##
## LEF for PtnCells ;
## created by Innovus v15.23-s045_1 on Sat Mar 21 00:23:52 2026
##

VERSION 5.8 ;

BUSBITCHARS "[]" ;
DIVIDERCHAR "/" ;

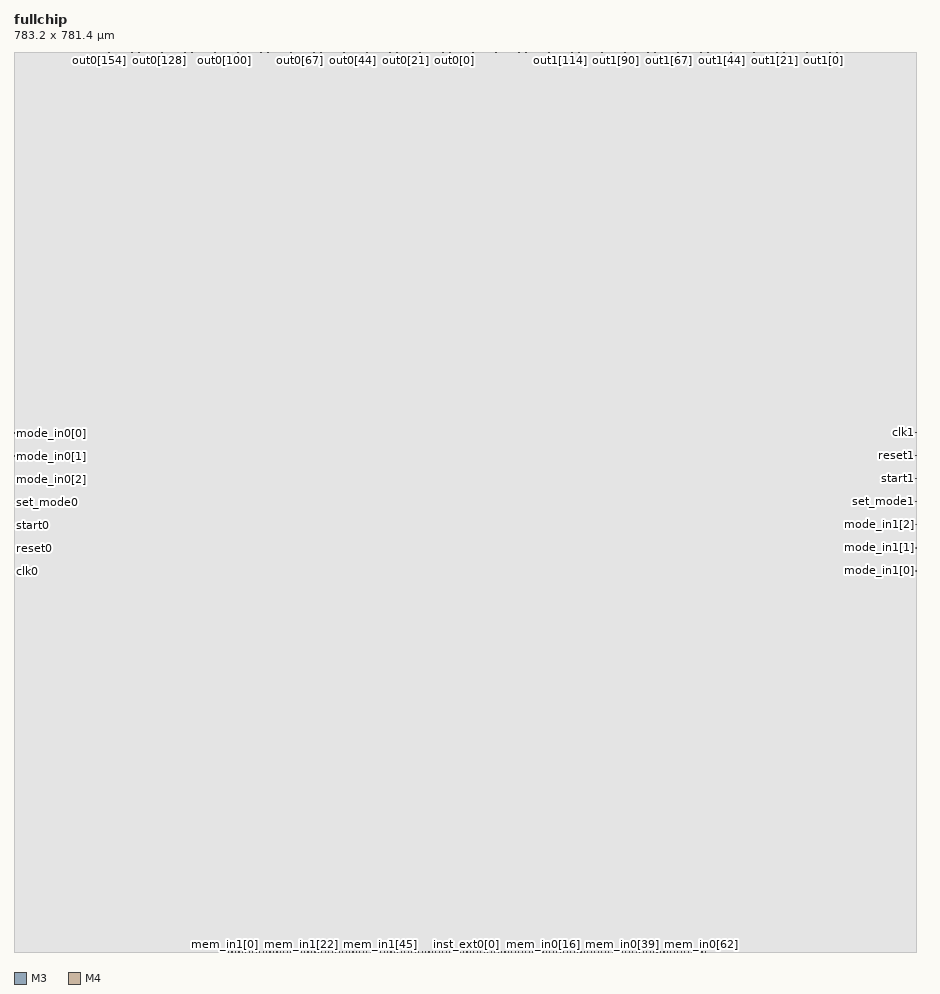
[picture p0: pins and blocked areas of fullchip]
MACRO fullchip
  CLASS BLOCK ;
  SIZE 783.2000 BY 781.4000 ;
  FOREIGN fullchip 0.0000 0.0000 ;
  ORIGIN 0 0 ;
  SYMMETRY X Y R90 ;
  PIN reset0
    DIRECTION INPUT ;
    USE SIGNAL ;
    PORT
      LAYER M3 ;
        RECT 0.0000 350.5500 0.5200 350.6500 ;
    END
  END reset0
  PIN reset1
    DIRECTION INPUT ;
    USE SIGNAL ;
    PORT
      LAYER M3 ;
        RECT 782.6800 430.7500 783.2000 430.8500 ;
    END
  END reset1
  PIN clk0
    DIRECTION INPUT ;
    USE SIGNAL ;
    PORT
      LAYER M3 ;
        RECT 0.0000 330.5500 0.5200 330.6500 ;
    END
  END clk0
  PIN clk1
    DIRECTION INPUT ;
    USE SIGNAL ;
    PORT
      LAYER M3 ;
        RECT 782.6800 450.7500 783.2000 450.8500 ;
    END
  END clk1
  PIN start0
    DIRECTION INPUT ;
    USE SIGNAL ;
    PORT
      LAYER M3 ;
        RECT 0.0000 370.5500 0.5200 370.6500 ;
    END
  END start0
  PIN start1
    DIRECTION INPUT ;
    USE SIGNAL ;
    PORT
      LAYER M3 ;
        RECT 782.6800 410.7500 783.2000 410.8500 ;
    END
  END start1
  PIN set_mode0
    DIRECTION INPUT ;
    USE SIGNAL ;
    PORT
      LAYER M3 ;
        RECT 0.0000 390.5500 0.5200 390.6500 ;
    END
  END set_mode0
  PIN set_mode1
    DIRECTION INPUT ;
    USE SIGNAL ;
    PORT
      LAYER M3 ;
        RECT 782.6800 390.7500 783.2000 390.8500 ;
    END
  END set_mode1
  PIN mode_in0[2]
    DIRECTION INPUT ;
    USE SIGNAL ;
    PORT
      LAYER M3 ;
        RECT 0.0000 410.5500 0.5200 410.6500 ;
    END
  END mode_in0[2]
  PIN mode_in0[1]
    DIRECTION INPUT ;
    USE SIGNAL ;
    PORT
      LAYER M3 ;
        RECT 0.0000 430.5500 0.5200 430.6500 ;
    END
  END mode_in0[1]
  PIN mode_in0[0]
    DIRECTION INPUT ;
    USE SIGNAL ;
    PORT
      LAYER M3 ;
        RECT 0.0000 450.5500 0.5200 450.6500 ;
    END
  END mode_in0[0]
  PIN mode_in1[2]
    DIRECTION INPUT ;
    USE SIGNAL ;
    PORT
      LAYER M3 ;
        RECT 782.6800 370.7500 783.2000 370.8500 ;
    END
  END mode_in1[2]
  PIN mode_in1[1]
    DIRECTION INPUT ;
    USE SIGNAL ;
    PORT
      LAYER M3 ;
        RECT 782.6800 350.7500 783.2000 350.8500 ;
    END
  END mode_in1[1]
  PIN mode_in1[0]
    DIRECTION INPUT ;
    USE SIGNAL ;
    PORT
      LAYER M3 ;
        RECT 782.6800 330.7500 783.2000 330.8500 ;
    END
  END mode_in1[0]
  PIN mem_in0[63]
    DIRECTION INPUT ;
    USE SIGNAL ;
    PORT
      LAYER M4 ;
        RECT 600.2500 0.0000 600.3500 0.5200 ;
    END
  END mem_in0[63]
  PIN mem_in0[62]
    DIRECTION INPUT ;
    USE SIGNAL ;
    PORT
      LAYER M4 ;
        RECT 597.2500 0.0000 597.3500 0.5200 ;
    END
  END mem_in0[62]
  PIN mem_in0[61]
    DIRECTION INPUT ;
    USE SIGNAL ;
    PORT
      LAYER M4 ;
        RECT 594.2500 0.0000 594.3500 0.5200 ;
    END
  END mem_in0[61]
  PIN mem_in0[60]
    DIRECTION INPUT ;
    USE SIGNAL ;
    PORT
      LAYER M4 ;
        RECT 591.2500 0.0000 591.3500 0.5200 ;
    END
  END mem_in0[60]
  PIN mem_in0[59]
    DIRECTION INPUT ;
    USE SIGNAL ;
    PORT
      LAYER M4 ;
        RECT 588.2500 0.0000 588.3500 0.5200 ;
    END
  END mem_in0[59]
  PIN mem_in0[58]
    DIRECTION INPUT ;
    USE SIGNAL ;
    PORT
      LAYER M4 ;
        RECT 585.2500 0.0000 585.3500 0.5200 ;
    END
  END mem_in0[58]
  PIN mem_in0[57]
    DIRECTION INPUT ;
    USE SIGNAL ;
    PORT
      LAYER M4 ;
        RECT 582.2500 0.0000 582.3500 0.5200 ;
    END
  END mem_in0[57]
  PIN mem_in0[56]
    DIRECTION INPUT ;
    USE SIGNAL ;
    PORT
      LAYER M4 ;
        RECT 579.2500 0.0000 579.3500 0.5200 ;
    END
  END mem_in0[56]
  PIN mem_in0[55]
    DIRECTION INPUT ;
    USE SIGNAL ;
    PORT
      LAYER M4 ;
        RECT 576.2500 0.0000 576.3500 0.5200 ;
    END
  END mem_in0[55]
  PIN mem_in0[54]
    DIRECTION INPUT ;
    USE SIGNAL ;
    PORT
      LAYER M4 ;
        RECT 573.2500 0.0000 573.3500 0.5200 ;
    END
  END mem_in0[54]
  PIN mem_in0[53]
    DIRECTION INPUT ;
    USE SIGNAL ;
    PORT
      LAYER M4 ;
        RECT 570.2500 0.0000 570.3500 0.5200 ;
    END
  END mem_in0[53]
  PIN mem_in0[52]
    DIRECTION INPUT ;
    USE SIGNAL ;
    PORT
      LAYER M4 ;
        RECT 567.2500 0.0000 567.3500 0.5200 ;
    END
  END mem_in0[52]
  PIN mem_in0[51]
    DIRECTION INPUT ;
    USE SIGNAL ;
    PORT
      LAYER M4 ;
        RECT 564.2500 0.0000 564.3500 0.5200 ;
    END
  END mem_in0[51]
  PIN mem_in0[50]
    DIRECTION INPUT ;
    USE SIGNAL ;
    PORT
      LAYER M4 ;
        RECT 561.2500 0.0000 561.3500 0.5200 ;
    END
  END mem_in0[50]
  PIN mem_in0[49]
    DIRECTION INPUT ;
    USE SIGNAL ;
    PORT
      LAYER M4 ;
        RECT 558.2500 0.0000 558.3500 0.5200 ;
    END
  END mem_in0[49]
  PIN mem_in0[48]
    DIRECTION INPUT ;
    USE SIGNAL ;
    PORT
      LAYER M4 ;
        RECT 555.2500 0.0000 555.3500 0.5200 ;
    END
  END mem_in0[48]
  PIN mem_in0[47]
    DIRECTION INPUT ;
    USE SIGNAL ;
    PORT
      LAYER M4 ;
        RECT 552.2500 0.0000 552.3500 0.5200 ;
    END
  END mem_in0[47]
  PIN mem_in0[46]
    DIRECTION INPUT ;
    USE SIGNAL ;
    PORT
      LAYER M4 ;
        RECT 549.2500 0.0000 549.3500 0.5200 ;
    END
  END mem_in0[46]
  PIN mem_in0[45]
    DIRECTION INPUT ;
    USE SIGNAL ;
    PORT
      LAYER M4 ;
        RECT 546.2500 0.0000 546.3500 0.5200 ;
    END
  END mem_in0[45]
  PIN mem_in0[44]
    DIRECTION INPUT ;
    USE SIGNAL ;
    PORT
      LAYER M4 ;
        RECT 543.2500 0.0000 543.3500 0.5200 ;
    END
  END mem_in0[44]
  PIN mem_in0[43]
    DIRECTION INPUT ;
    USE SIGNAL ;
    PORT
      LAYER M4 ;
        RECT 540.2500 0.0000 540.3500 0.5200 ;
    END
  END mem_in0[43]
  PIN mem_in0[42]
    DIRECTION INPUT ;
    USE SIGNAL ;
    PORT
      LAYER M4 ;
        RECT 537.2500 0.0000 537.3500 0.5200 ;
    END
  END mem_in0[42]
  PIN mem_in0[41]
    DIRECTION INPUT ;
    USE SIGNAL ;
    PORT
      LAYER M4 ;
        RECT 534.2500 0.0000 534.3500 0.5200 ;
    END
  END mem_in0[41]
  PIN mem_in0[40]
    DIRECTION INPUT ;
    USE SIGNAL ;
    PORT
      LAYER M4 ;
        RECT 531.2500 0.0000 531.3500 0.5200 ;
    END
  END mem_in0[40]
  PIN mem_in0[39]
    DIRECTION INPUT ;
    USE SIGNAL ;
    PORT
      LAYER M4 ;
        RECT 528.2500 0.0000 528.3500 0.5200 ;
    END
  END mem_in0[39]
  PIN mem_in0[38]
    DIRECTION INPUT ;
    USE SIGNAL ;
    PORT
      LAYER M4 ;
        RECT 525.2500 0.0000 525.3500 0.5200 ;
    END
  END mem_in0[38]
  PIN mem_in0[37]
    DIRECTION INPUT ;
    USE SIGNAL ;
    PORT
      LAYER M4 ;
        RECT 522.2500 0.0000 522.3500 0.5200 ;
    END
  END mem_in0[37]
  PIN mem_in0[36]
    DIRECTION INPUT ;
    USE SIGNAL ;
    PORT
      LAYER M4 ;
        RECT 519.2500 0.0000 519.3500 0.5200 ;
    END
  END mem_in0[36]
  PIN mem_in0[35]
    DIRECTION INPUT ;
    USE SIGNAL ;
    PORT
      LAYER M4 ;
        RECT 516.2500 0.0000 516.3500 0.5200 ;
    END
  END mem_in0[35]
  PIN mem_in0[34]
    DIRECTION INPUT ;
    USE SIGNAL ;
    PORT
      LAYER M4 ;
        RECT 513.2500 0.0000 513.3500 0.5200 ;
    END
  END mem_in0[34]
  PIN mem_in0[33]
    DIRECTION INPUT ;
    USE SIGNAL ;
    PORT
      LAYER M4 ;
        RECT 510.2500 0.0000 510.3500 0.5200 ;
    END
  END mem_in0[33]
  PIN mem_in0[32]
    DIRECTION INPUT ;
    USE SIGNAL ;
    PORT
      LAYER M4 ;
        RECT 507.2500 0.0000 507.3500 0.5200 ;
    END
  END mem_in0[32]
  PIN mem_in0[31]
    DIRECTION INPUT ;
    USE SIGNAL ;
    PORT
      LAYER M4 ;
        RECT 504.2500 0.0000 504.3500 0.5200 ;
    END
  END mem_in0[31]
  PIN mem_in0[30]
    DIRECTION INPUT ;
    USE SIGNAL ;
    PORT
      LAYER M4 ;
        RECT 501.2500 0.0000 501.3500 0.5200 ;
    END
  END mem_in0[30]
  PIN mem_in0[29]
    DIRECTION INPUT ;
    USE SIGNAL ;
    PORT
      LAYER M4 ;
        RECT 498.2500 0.0000 498.3500 0.5200 ;
    END
  END mem_in0[29]
  PIN mem_in0[28]
    DIRECTION INPUT ;
    USE SIGNAL ;
    PORT
      LAYER M4 ;
        RECT 495.2500 0.0000 495.3500 0.5200 ;
    END
  END mem_in0[28]
  PIN mem_in0[27]
    DIRECTION INPUT ;
    USE SIGNAL ;
    PORT
      LAYER M4 ;
        RECT 492.2500 0.0000 492.3500 0.5200 ;
    END
  END mem_in0[27]
  PIN mem_in0[26]
    DIRECTION INPUT ;
    USE SIGNAL ;
    PORT
      LAYER M4 ;
        RECT 489.2500 0.0000 489.3500 0.5200 ;
    END
  END mem_in0[26]
  PIN mem_in0[25]
    DIRECTION INPUT ;
    USE SIGNAL ;
    PORT
      LAYER M4 ;
        RECT 486.2500 0.0000 486.3500 0.5200 ;
    END
  END mem_in0[25]
  PIN mem_in0[24]
    DIRECTION INPUT ;
    USE SIGNAL ;
    PORT
      LAYER M4 ;
        RECT 483.2500 0.0000 483.3500 0.5200 ;
    END
  END mem_in0[24]
  PIN mem_in0[23]
    DIRECTION INPUT ;
    USE SIGNAL ;
    PORT
      LAYER M4 ;
        RECT 480.2500 0.0000 480.3500 0.5200 ;
    END
  END mem_in0[23]
  PIN mem_in0[22]
    DIRECTION INPUT ;
    USE SIGNAL ;
    PORT
      LAYER M4 ;
        RECT 477.2500 0.0000 477.3500 0.5200 ;
    END
  END mem_in0[22]
  PIN mem_in0[21]
    DIRECTION INPUT ;
    USE SIGNAL ;
    PORT
      LAYER M4 ;
        RECT 474.2500 0.0000 474.3500 0.5200 ;
    END
  END mem_in0[21]
  PIN mem_in0[20]
    DIRECTION INPUT ;
    USE SIGNAL ;
    PORT
      LAYER M4 ;
        RECT 471.2500 0.0000 471.3500 0.5200 ;
    END
  END mem_in0[20]
  PIN mem_in0[19]
    DIRECTION INPUT ;
    USE SIGNAL ;
    PORT
      LAYER M4 ;
        RECT 468.2500 0.0000 468.3500 0.5200 ;
    END
  END mem_in0[19]
  PIN mem_in0[18]
    DIRECTION INPUT ;
    USE SIGNAL ;
    PORT
      LAYER M4 ;
        RECT 465.2500 0.0000 465.3500 0.5200 ;
    END
  END mem_in0[18]
  PIN mem_in0[17]
    DIRECTION INPUT ;
    USE SIGNAL ;
    PORT
      LAYER M4 ;
        RECT 462.2500 0.0000 462.3500 0.5200 ;
    END
  END mem_in0[17]
  PIN mem_in0[16]
    DIRECTION INPUT ;
    USE SIGNAL ;
    PORT
      LAYER M4 ;
        RECT 459.2500 0.0000 459.3500 0.5200 ;
    END
  END mem_in0[16]
  PIN mem_in0[15]
    DIRECTION INPUT ;
    USE SIGNAL ;
    PORT
      LAYER M4 ;
        RECT 456.2500 0.0000 456.3500 0.5200 ;
    END
  END mem_in0[15]
  PIN mem_in0[14]
    DIRECTION INPUT ;
    USE SIGNAL ;
    PORT
      LAYER M4 ;
        RECT 453.2500 0.0000 453.3500 0.5200 ;
    END
  END mem_in0[14]
  PIN mem_in0[13]
    DIRECTION INPUT ;
    USE SIGNAL ;
    PORT
      LAYER M4 ;
        RECT 450.2500 0.0000 450.3500 0.5200 ;
    END
  END mem_in0[13]
  PIN mem_in0[12]
    DIRECTION INPUT ;
    USE SIGNAL ;
    PORT
      LAYER M4 ;
        RECT 447.2500 0.0000 447.3500 0.5200 ;
    END
  END mem_in0[12]
  PIN mem_in0[11]
    DIRECTION INPUT ;
    USE SIGNAL ;
    PORT
      LAYER M4 ;
        RECT 444.2500 0.0000 444.3500 0.5200 ;
    END
  END mem_in0[11]
  PIN mem_in0[10]
    DIRECTION INPUT ;
    USE SIGNAL ;
    PORT
      LAYER M4 ;
        RECT 441.2500 0.0000 441.3500 0.5200 ;
    END
  END mem_in0[10]
  PIN mem_in0[9]
    DIRECTION INPUT ;
    USE SIGNAL ;
    PORT
      LAYER M4 ;
        RECT 438.2500 0.0000 438.3500 0.5200 ;
    END
  END mem_in0[9]
  PIN mem_in0[8]
    DIRECTION INPUT ;
    USE SIGNAL ;
    PORT
      LAYER M4 ;
        RECT 435.2500 0.0000 435.3500 0.5200 ;
    END
  END mem_in0[8]
  PIN mem_in0[7]
    DIRECTION INPUT ;
    USE SIGNAL ;
    PORT
      LAYER M4 ;
        RECT 432.2500 0.0000 432.3500 0.5200 ;
    END
  END mem_in0[7]
  PIN mem_in0[6]
    DIRECTION INPUT ;
    USE SIGNAL ;
    PORT
      LAYER M4 ;
        RECT 429.2500 0.0000 429.3500 0.5200 ;
    END
  END mem_in0[6]
  PIN mem_in0[5]
    DIRECTION INPUT ;
    USE SIGNAL ;
    PORT
      LAYER M4 ;
        RECT 426.2500 0.0000 426.3500 0.5200 ;
    END
  END mem_in0[5]
  PIN mem_in0[4]
    DIRECTION INPUT ;
    USE SIGNAL ;
    PORT
      LAYER M4 ;
        RECT 423.2500 0.0000 423.3500 0.5200 ;
    END
  END mem_in0[4]
  PIN mem_in0[3]
    DIRECTION INPUT ;
    USE SIGNAL ;
    PORT
      LAYER M4 ;
        RECT 420.2500 0.0000 420.3500 0.5200 ;
    END
  END mem_in0[3]
  PIN mem_in0[2]
    DIRECTION INPUT ;
    USE SIGNAL ;
    PORT
      LAYER M4 ;
        RECT 417.2500 0.0000 417.3500 0.5200 ;
    END
  END mem_in0[2]
  PIN mem_in0[1]
    DIRECTION INPUT ;
    USE SIGNAL ;
    PORT
      LAYER M4 ;
        RECT 414.2500 0.0000 414.3500 0.5200 ;
    END
  END mem_in0[1]
  PIN mem_in0[0]
    DIRECTION INPUT ;
    USE SIGNAL ;
    PORT
      LAYER M4 ;
        RECT 411.2500 0.0000 411.3500 0.5200 ;
    END
  END mem_in0[0]
  PIN mem_in1[63]
    DIRECTION INPUT ;
    USE SIGNAL ;
    PORT
      LAYER M4 ;
        RECT 372.2500 0.0000 372.3500 0.5200 ;
    END
  END mem_in1[63]
  PIN mem_in1[62]
    DIRECTION INPUT ;
    USE SIGNAL ;
    PORT
      LAYER M4 ;
        RECT 369.2500 0.0000 369.3500 0.5200 ;
    END
  END mem_in1[62]
  PIN mem_in1[61]
    DIRECTION INPUT ;
    USE SIGNAL ;
    PORT
      LAYER M4 ;
        RECT 366.2500 0.0000 366.3500 0.5200 ;
    END
  END mem_in1[61]
  PIN mem_in1[60]
    DIRECTION INPUT ;
    USE SIGNAL ;
    PORT
      LAYER M4 ;
        RECT 363.2500 0.0000 363.3500 0.5200 ;
    END
  END mem_in1[60]
  PIN mem_in1[59]
    DIRECTION INPUT ;
    USE SIGNAL ;
    PORT
      LAYER M4 ;
        RECT 360.2500 0.0000 360.3500 0.5200 ;
    END
  END mem_in1[59]
  PIN mem_in1[58]
    DIRECTION INPUT ;
    USE SIGNAL ;
    PORT
      LAYER M4 ;
        RECT 357.2500 0.0000 357.3500 0.5200 ;
    END
  END mem_in1[58]
  PIN mem_in1[57]
    DIRECTION INPUT ;
    USE SIGNAL ;
    PORT
      LAYER M4 ;
        RECT 354.2500 0.0000 354.3500 0.5200 ;
    END
  END mem_in1[57]
  PIN mem_in1[56]
    DIRECTION INPUT ;
    USE SIGNAL ;
    PORT
      LAYER M4 ;
        RECT 351.2500 0.0000 351.3500 0.5200 ;
    END
  END mem_in1[56]
  PIN mem_in1[55]
    DIRECTION INPUT ;
    USE SIGNAL ;
    PORT
      LAYER M4 ;
        RECT 348.2500 0.0000 348.3500 0.5200 ;
    END
  END mem_in1[55]
  PIN mem_in1[54]
    DIRECTION INPUT ;
    USE SIGNAL ;
    PORT
      LAYER M4 ;
        RECT 345.2500 0.0000 345.3500 0.5200 ;
    END
  END mem_in1[54]
  PIN mem_in1[53]
    DIRECTION INPUT ;
    USE SIGNAL ;
    PORT
      LAYER M4 ;
        RECT 342.2500 0.0000 342.3500 0.5200 ;
    END
  END mem_in1[53]
  PIN mem_in1[52]
    DIRECTION INPUT ;
    USE SIGNAL ;
    PORT
      LAYER M4 ;
        RECT 339.2500 0.0000 339.3500 0.5200 ;
    END
  END mem_in1[52]
  PIN mem_in1[51]
    DIRECTION INPUT ;
    USE SIGNAL ;
    PORT
      LAYER M4 ;
        RECT 336.2500 0.0000 336.3500 0.5200 ;
    END
  END mem_in1[51]
  PIN mem_in1[50]
    DIRECTION INPUT ;
    USE SIGNAL ;
    PORT
      LAYER M4 ;
        RECT 333.2500 0.0000 333.3500 0.5200 ;
    END
  END mem_in1[50]
  PIN mem_in1[49]
    DIRECTION INPUT ;
    USE SIGNAL ;
    PORT
      LAYER M4 ;
        RECT 330.2500 0.0000 330.3500 0.5200 ;
    END
  END mem_in1[49]
  PIN mem_in1[48]
    DIRECTION INPUT ;
    USE SIGNAL ;
    PORT
      LAYER M4 ;
        RECT 327.2500 0.0000 327.3500 0.5200 ;
    END
  END mem_in1[48]
  PIN mem_in1[47]
    DIRECTION INPUT ;
    USE SIGNAL ;
    PORT
      LAYER M4 ;
        RECT 324.2500 0.0000 324.3500 0.5200 ;
    END
  END mem_in1[47]
  PIN mem_in1[46]
    DIRECTION INPUT ;
    USE SIGNAL ;
    PORT
      LAYER M4 ;
        RECT 321.2500 0.0000 321.3500 0.5200 ;
    END
  END mem_in1[46]
  PIN mem_in1[45]
    DIRECTION INPUT ;
    USE SIGNAL ;
    PORT
      LAYER M4 ;
        RECT 318.2500 0.0000 318.3500 0.5200 ;
    END
  END mem_in1[45]
  PIN mem_in1[44]
    DIRECTION INPUT ;
    USE SIGNAL ;
    PORT
      LAYER M4 ;
        RECT 315.2500 0.0000 315.3500 0.5200 ;
    END
  END mem_in1[44]
  PIN mem_in1[43]
    DIRECTION INPUT ;
    USE SIGNAL ;
    PORT
      LAYER M4 ;
        RECT 312.2500 0.0000 312.3500 0.5200 ;
    END
  END mem_in1[43]
  PIN mem_in1[42]
    DIRECTION INPUT ;
    USE SIGNAL ;
    PORT
      LAYER M4 ;
        RECT 309.2500 0.0000 309.3500 0.5200 ;
    END
  END mem_in1[42]
  PIN mem_in1[41]
    DIRECTION INPUT ;
    USE SIGNAL ;
    PORT
      LAYER M4 ;
        RECT 306.2500 0.0000 306.3500 0.5200 ;
    END
  END mem_in1[41]
  PIN mem_in1[40]
    DIRECTION INPUT ;
    USE SIGNAL ;
    PORT
      LAYER M4 ;
        RECT 303.2500 0.0000 303.3500 0.5200 ;
    END
  END mem_in1[40]
  PIN mem_in1[39]
    DIRECTION INPUT ;
    USE SIGNAL ;
    PORT
      LAYER M4 ;
        RECT 300.2500 0.0000 300.3500 0.5200 ;
    END
  END mem_in1[39]
  PIN mem_in1[38]
    DIRECTION INPUT ;
    USE SIGNAL ;
    PORT
      LAYER M4 ;
        RECT 297.2500 0.0000 297.3500 0.5200 ;
    END
  END mem_in1[38]
  PIN mem_in1[37]
    DIRECTION INPUT ;
    USE SIGNAL ;
    PORT
      LAYER M4 ;
        RECT 294.2500 0.0000 294.3500 0.5200 ;
    END
  END mem_in1[37]
  PIN mem_in1[36]
    DIRECTION INPUT ;
    USE SIGNAL ;
    PORT
      LAYER M4 ;
        RECT 291.2500 0.0000 291.3500 0.5200 ;
    END
  END mem_in1[36]
  PIN mem_in1[35]
    DIRECTION INPUT ;
    USE SIGNAL ;
    PORT
      LAYER M4 ;
        RECT 288.2500 0.0000 288.3500 0.5200 ;
    END
  END mem_in1[35]
  PIN mem_in1[34]
    DIRECTION INPUT ;
    USE SIGNAL ;
    PORT
      LAYER M4 ;
        RECT 285.2500 0.0000 285.3500 0.5200 ;
    END
  END mem_in1[34]
  PIN mem_in1[33]
    DIRECTION INPUT ;
    USE SIGNAL ;
    PORT
      LAYER M4 ;
        RECT 282.2500 0.0000 282.3500 0.5200 ;
    END
  END mem_in1[33]
  PIN mem_in1[32]
    DIRECTION INPUT ;
    USE SIGNAL ;
    PORT
      LAYER M4 ;
        RECT 279.2500 0.0000 279.3500 0.5200 ;
    END
  END mem_in1[32]
  PIN mem_in1[31]
    DIRECTION INPUT ;
    USE SIGNAL ;
    PORT
      LAYER M4 ;
        RECT 276.2500 0.0000 276.3500 0.5200 ;
    END
  END mem_in1[31]
  PIN mem_in1[30]
    DIRECTION INPUT ;
    USE SIGNAL ;
    PORT
      LAYER M4 ;
        RECT 273.2500 0.0000 273.3500 0.5200 ;
    END
  END mem_in1[30]
  PIN mem_in1[29]
    DIRECTION INPUT ;
    USE SIGNAL ;
    PORT
      LAYER M4 ;
        RECT 270.2500 0.0000 270.3500 0.5200 ;
    END
  END mem_in1[29]
  PIN mem_in1[28]
    DIRECTION INPUT ;
    USE SIGNAL ;
    PORT
      LAYER M4 ;
        RECT 267.2500 0.0000 267.3500 0.5200 ;
    END
  END mem_in1[28]
  PIN mem_in1[27]
    DIRECTION INPUT ;
    USE SIGNAL ;
    PORT
      LAYER M4 ;
        RECT 264.2500 0.0000 264.3500 0.5200 ;
    END
  END mem_in1[27]
  PIN mem_in1[26]
    DIRECTION INPUT ;
    USE SIGNAL ;
    PORT
      LAYER M4 ;
        RECT 261.2500 0.0000 261.3500 0.5200 ;
    END
  END mem_in1[26]
  PIN mem_in1[25]
    DIRECTION INPUT ;
    USE SIGNAL ;
    PORT
      LAYER M4 ;
        RECT 258.2500 0.0000 258.3500 0.5200 ;
    END
  END mem_in1[25]
  PIN mem_in1[24]
    DIRECTION INPUT ;
    USE SIGNAL ;
    PORT
      LAYER M4 ;
        RECT 255.2500 0.0000 255.3500 0.5200 ;
    END
  END mem_in1[24]
  PIN mem_in1[23]
    DIRECTION INPUT ;
    USE SIGNAL ;
    PORT
      LAYER M4 ;
        RECT 252.2500 0.0000 252.3500 0.5200 ;
    END
  END mem_in1[23]
  PIN mem_in1[22]
    DIRECTION INPUT ;
    USE SIGNAL ;
    PORT
      LAYER M4 ;
        RECT 249.2500 0.0000 249.3500 0.5200 ;
    END
  END mem_in1[22]
  PIN mem_in1[21]
    DIRECTION INPUT ;
    USE SIGNAL ;
    PORT
      LAYER M4 ;
        RECT 246.2500 0.0000 246.3500 0.5200 ;
    END
  END mem_in1[21]
  PIN mem_in1[20]
    DIRECTION INPUT ;
    USE SIGNAL ;
    PORT
      LAYER M4 ;
        RECT 243.2500 0.0000 243.3500 0.5200 ;
    END
  END mem_in1[20]
  PIN mem_in1[19]
    DIRECTION INPUT ;
    USE SIGNAL ;
    PORT
      LAYER M4 ;
        RECT 240.2500 0.0000 240.3500 0.5200 ;
    END
  END mem_in1[19]
  PIN mem_in1[18]
    DIRECTION INPUT ;
    USE SIGNAL ;
    PORT
      LAYER M4 ;
        RECT 237.2500 0.0000 237.3500 0.5200 ;
    END
  END mem_in1[18]
  PIN mem_in1[17]
    DIRECTION INPUT ;
    USE SIGNAL ;
    PORT
      LAYER M4 ;
        RECT 234.2500 0.0000 234.3500 0.5200 ;
    END
  END mem_in1[17]
  PIN mem_in1[16]
    DIRECTION INPUT ;
    USE SIGNAL ;
    PORT
      LAYER M4 ;
        RECT 231.2500 0.0000 231.3500 0.5200 ;
    END
  END mem_in1[16]
  PIN mem_in1[15]
    DIRECTION INPUT ;
    USE SIGNAL ;
    PORT
      LAYER M4 ;
        RECT 228.2500 0.0000 228.3500 0.5200 ;
    END
  END mem_in1[15]
  PIN mem_in1[14]
    DIRECTION INPUT ;
    USE SIGNAL ;
    PORT
      LAYER M4 ;
        RECT 225.2500 0.0000 225.3500 0.5200 ;
    END
  END mem_in1[14]
  PIN mem_in1[13]
    DIRECTION INPUT ;
    USE SIGNAL ;
    PORT
      LAYER M4 ;
        RECT 222.2500 0.0000 222.3500 0.5200 ;
    END
  END mem_in1[13]
  PIN mem_in1[12]
    DIRECTION INPUT ;
    USE SIGNAL ;
    PORT
      LAYER M4 ;
        RECT 219.2500 0.0000 219.3500 0.5200 ;
    END
  END mem_in1[12]
  PIN mem_in1[11]
    DIRECTION INPUT ;
    USE SIGNAL ;
    PORT
      LAYER M4 ;
        RECT 216.2500 0.0000 216.3500 0.5200 ;
    END
  END mem_in1[11]
  PIN mem_in1[10]
    DIRECTION INPUT ;
    USE SIGNAL ;
    PORT
      LAYER M4 ;
        RECT 213.2500 0.0000 213.3500 0.5200 ;
    END
  END mem_in1[10]
  PIN mem_in1[9]
    DIRECTION INPUT ;
    USE SIGNAL ;
    PORT
      LAYER M4 ;
        RECT 210.2500 0.0000 210.3500 0.5200 ;
    END
  END mem_in1[9]
  PIN mem_in1[8]
    DIRECTION INPUT ;
    USE SIGNAL ;
    PORT
      LAYER M4 ;
        RECT 207.2500 0.0000 207.3500 0.5200 ;
    END
  END mem_in1[8]
  PIN mem_in1[7]
    DIRECTION INPUT ;
    USE SIGNAL ;
    PORT
      LAYER M4 ;
        RECT 204.2500 0.0000 204.3500 0.5200 ;
    END
  END mem_in1[7]
  PIN mem_in1[6]
    DIRECTION INPUT ;
    USE SIGNAL ;
    PORT
      LAYER M4 ;
        RECT 201.2500 0.0000 201.3500 0.5200 ;
    END
  END mem_in1[6]
  PIN mem_in1[5]
    DIRECTION INPUT ;
    USE SIGNAL ;
    PORT
      LAYER M4 ;
        RECT 198.2500 0.0000 198.3500 0.5200 ;
    END
  END mem_in1[5]
  PIN mem_in1[4]
    DIRECTION INPUT ;
    USE SIGNAL ;
    PORT
      LAYER M4 ;
        RECT 195.2500 0.0000 195.3500 0.5200 ;
    END
  END mem_in1[4]
  PIN mem_in1[3]
    DIRECTION INPUT ;
    USE SIGNAL ;
    PORT
      LAYER M4 ;
        RECT 192.2500 0.0000 192.3500 0.5200 ;
    END
  END mem_in1[3]
  PIN mem_in1[2]
    DIRECTION INPUT ;
    USE SIGNAL ;
    PORT
      LAYER M4 ;
        RECT 189.2500 0.0000 189.3500 0.5200 ;
    END
  END mem_in1[2]
  PIN mem_in1[1]
    DIRECTION INPUT ;
    USE SIGNAL ;
    PORT
      LAYER M4 ;
        RECT 186.2500 0.0000 186.3500 0.5200 ;
    END
  END mem_in1[1]
  PIN mem_in1[0]
    DIRECTION INPUT ;
    USE SIGNAL ;
    PORT
      LAYER M4 ;
        RECT 183.2500 0.0000 183.3500 0.5200 ;
    END
  END mem_in1[0]
  PIN inst_ext0[5]
    DIRECTION INPUT ;
    USE SIGNAL ;
    PORT
      LAYER M4 ;
        RECT 408.2500 0.0000 408.3500 0.5200 ;
    END
  END inst_ext0[5]
  PIN inst_ext0[4]
    DIRECTION INPUT ;
    USE SIGNAL ;
    PORT
      LAYER M4 ;
        RECT 405.2500 0.0000 405.3500 0.5200 ;
    END
  END inst_ext0[4]
  PIN inst_ext0[3]
    DIRECTION INPUT ;
    USE SIGNAL ;
    PORT
      LAYER M4 ;
        RECT 402.2500 0.0000 402.3500 0.5200 ;
    END
  END inst_ext0[3]
  PIN inst_ext0[2]
    DIRECTION INPUT ;
    USE SIGNAL ;
    PORT
      LAYER M4 ;
        RECT 399.2500 0.0000 399.3500 0.5200 ;
    END
  END inst_ext0[2]
  PIN inst_ext0[1]
    DIRECTION INPUT ;
    USE SIGNAL ;
    PORT
      LAYER M4 ;
        RECT 396.2500 0.0000 396.3500 0.5200 ;
    END
  END inst_ext0[1]
  PIN inst_ext0[0]
    DIRECTION INPUT ;
    USE SIGNAL ;
    PORT
      LAYER M4 ;
        RECT 393.2500 0.0000 393.3500 0.5200 ;
    END
  END inst_ext0[0]
  PIN inst_ext1[5]
    DIRECTION INPUT ;
    USE SIGNAL ;
    PORT
      LAYER M4 ;
        RECT 390.2500 0.0000 390.3500 0.5200 ;
    END
  END inst_ext1[5]
  PIN inst_ext1[4]
    DIRECTION INPUT ;
    USE SIGNAL ;
    PORT
      LAYER M4 ;
        RECT 387.2500 0.0000 387.3500 0.5200 ;
    END
  END inst_ext1[4]
  PIN inst_ext1[3]
    DIRECTION INPUT ;
    USE SIGNAL ;
    PORT
      LAYER M4 ;
        RECT 384.2500 0.0000 384.3500 0.5200 ;
    END
  END inst_ext1[3]
  PIN inst_ext1[2]
    DIRECTION INPUT ;
    USE SIGNAL ;
    PORT
      LAYER M4 ;
        RECT 381.2500 0.0000 381.3500 0.5200 ;
    END
  END inst_ext1[2]
  PIN inst_ext1[1]
    DIRECTION INPUT ;
    USE SIGNAL ;
    PORT
      LAYER M4 ;
        RECT 378.2500 0.0000 378.3500 0.5200 ;
    END
  END inst_ext1[1]
  PIN inst_ext1[0]
    DIRECTION INPUT ;
    USE SIGNAL ;
    PORT
      LAYER M4 ;
        RECT 375.2500 0.0000 375.3500 0.5200 ;
    END
  END inst_ext1[0]
  PIN out0[159]
    DIRECTION OUTPUT ;
    USE SIGNAL ;
    PORT
      LAYER M4 ;
        RECT 64.4500 780.8800 64.5500 781.4000 ;
    END
  END out0[159]
  PIN out0[158]
    DIRECTION OUTPUT ;
    USE SIGNAL ;
    PORT
      LAYER M4 ;
        RECT 66.4500 780.8800 66.5500 781.4000 ;
    END
  END out0[158]
  PIN out0[157]
    DIRECTION OUTPUT ;
    USE SIGNAL ;
    PORT
      LAYER M4 ;
        RECT 68.4500 780.8800 68.5500 781.4000 ;
    END
  END out0[157]
  PIN out0[156]
    DIRECTION OUTPUT ;
    USE SIGNAL ;
    PORT
      LAYER M4 ;
        RECT 70.4500 780.8800 70.5500 781.4000 ;
    END
  END out0[156]
  PIN out0[155]
    DIRECTION OUTPUT ;
    USE SIGNAL ;
    PORT
      LAYER M4 ;
        RECT 72.4500 780.8800 72.5500 781.4000 ;
    END
  END out0[155]
  PIN out0[154]
    DIRECTION OUTPUT ;
    USE SIGNAL ;
    PORT
      LAYER M4 ;
        RECT 74.4500 780.8800 74.5500 781.4000 ;
    END
  END out0[154]
  PIN out0[153]
    DIRECTION OUTPUT ;
    USE SIGNAL ;
    PORT
      LAYER M4 ;
        RECT 76.4500 780.8800 76.5500 781.4000 ;
    END
  END out0[153]
  PIN out0[152]
    DIRECTION OUTPUT ;
    USE SIGNAL ;
    PORT
      LAYER M4 ;
        RECT 78.4500 780.8800 78.5500 781.4000 ;
    END
  END out0[152]
  PIN out0[151]
    DIRECTION OUTPUT ;
    USE SIGNAL ;
    PORT
      LAYER M4 ;
        RECT 80.4500 780.8800 80.5500 781.4000 ;
    END
  END out0[151]
  PIN out0[150]
    DIRECTION OUTPUT ;
    USE SIGNAL ;
    PORT
      LAYER M4 ;
        RECT 82.4500 780.8800 82.5500 781.4000 ;
    END
  END out0[150]
  PIN out0[149]
    DIRECTION OUTPUT ;
    USE SIGNAL ;
    PORT
      LAYER M4 ;
        RECT 84.4500 780.8800 84.5500 781.4000 ;
    END
  END out0[149]
  PIN out0[148]
    DIRECTION OUTPUT ;
    USE SIGNAL ;
    PORT
      LAYER M4 ;
        RECT 86.4500 780.8800 86.5500 781.4000 ;
    END
  END out0[148]
  PIN out0[147]
    DIRECTION OUTPUT ;
    USE SIGNAL ;
    PORT
      LAYER M4 ;
        RECT 88.4500 780.8800 88.5500 781.4000 ;
    END
  END out0[147]
  PIN out0[146]
    DIRECTION OUTPUT ;
    USE SIGNAL ;
    PORT
      LAYER M4 ;
        RECT 90.4500 780.8800 90.5500 781.4000 ;
    END
  END out0[146]
  PIN out0[145]
    DIRECTION OUTPUT ;
    USE SIGNAL ;
    PORT
      LAYER M4 ;
        RECT 92.4500 780.8800 92.5500 781.4000 ;
    END
  END out0[145]
  PIN out0[144]
    DIRECTION OUTPUT ;
    USE SIGNAL ;
    PORT
      LAYER M4 ;
        RECT 94.4500 780.8800 94.5500 781.4000 ;
    END
  END out0[144]
  PIN out0[143]
    DIRECTION OUTPUT ;
    USE SIGNAL ;
    PORT
      LAYER M4 ;
        RECT 96.4500 780.8800 96.5500 781.4000 ;
    END
  END out0[143]
  PIN out0[142]
    DIRECTION OUTPUT ;
    USE SIGNAL ;
    PORT
      LAYER M4 ;
        RECT 98.4500 780.8800 98.5500 781.4000 ;
    END
  END out0[142]
  PIN out0[141]
    DIRECTION OUTPUT ;
    USE SIGNAL ;
    PORT
      LAYER M4 ;
        RECT 100.4500 780.8800 100.5500 781.4000 ;
    END
  END out0[141]
  PIN out0[140]
    DIRECTION OUTPUT ;
    USE SIGNAL ;
    PORT
      LAYER M4 ;
        RECT 102.4500 780.8800 102.5500 781.4000 ;
    END
  END out0[140]
  PIN out0[139]
    DIRECTION OUTPUT ;
    USE SIGNAL ;
    PORT
      LAYER M4 ;
        RECT 104.4500 780.8800 104.5500 781.4000 ;
    END
  END out0[139]
  PIN out0[138]
    DIRECTION OUTPUT ;
    USE SIGNAL ;
    PORT
      LAYER M4 ;
        RECT 106.4500 780.8800 106.5500 781.4000 ;
    END
  END out0[138]
  PIN out0[137]
    DIRECTION OUTPUT ;
    USE SIGNAL ;
    PORT
      LAYER M4 ;
        RECT 108.4500 780.8800 108.5500 781.4000 ;
    END
  END out0[137]
  PIN out0[136]
    DIRECTION OUTPUT ;
    USE SIGNAL ;
    PORT
      LAYER M4 ;
        RECT 110.4500 780.8800 110.5500 781.4000 ;
    END
  END out0[136]
  PIN out0[135]
    DIRECTION OUTPUT ;
    USE SIGNAL ;
    PORT
      LAYER M4 ;
        RECT 112.4500 780.8800 112.5500 781.4000 ;
    END
  END out0[135]
  PIN out0[134]
    DIRECTION OUTPUT ;
    USE SIGNAL ;
    PORT
      LAYER M4 ;
        RECT 114.4500 780.8800 114.5500 781.4000 ;
    END
  END out0[134]
  PIN out0[133]
    DIRECTION OUTPUT ;
    USE SIGNAL ;
    PORT
      LAYER M4 ;
        RECT 116.4500 780.8800 116.5500 781.4000 ;
    END
  END out0[133]
  PIN out0[132]
    DIRECTION OUTPUT ;
    USE SIGNAL ;
    PORT
      LAYER M4 ;
        RECT 118.4500 780.8800 118.5500 781.4000 ;
    END
  END out0[132]
  PIN out0[131]
    DIRECTION OUTPUT ;
    USE SIGNAL ;
    PORT
      LAYER M4 ;
        RECT 120.4500 780.8800 120.5500 781.4000 ;
    END
  END out0[131]
  PIN out0[130]
    DIRECTION OUTPUT ;
    USE SIGNAL ;
    PORT
      LAYER M4 ;
        RECT 122.4500 780.8800 122.5500 781.4000 ;
    END
  END out0[130]
  PIN out0[129]
    DIRECTION OUTPUT ;
    USE SIGNAL ;
    PORT
      LAYER M4 ;
        RECT 124.4500 780.8800 124.5500 781.4000 ;
    END
  END out0[129]
  PIN out0[128]
    DIRECTION OUTPUT ;
    USE SIGNAL ;
    PORT
      LAYER M4 ;
        RECT 126.4500 780.8800 126.5500 781.4000 ;
    END
  END out0[128]
  PIN out0[127]
    DIRECTION OUTPUT ;
    USE SIGNAL ;
    PORT
      LAYER M4 ;
        RECT 128.4500 780.8800 128.5500 781.4000 ;
    END
  END out0[127]
  PIN out0[126]
    DIRECTION OUTPUT ;
    USE SIGNAL ;
    PORT
      LAYER M4 ;
        RECT 130.4500 780.8800 130.5500 781.4000 ;
    END
  END out0[126]
  PIN out0[125]
    DIRECTION OUTPUT ;
    USE SIGNAL ;
    PORT
      LAYER M4 ;
        RECT 132.4500 780.8800 132.5500 781.4000 ;
    END
  END out0[125]
  PIN out0[124]
    DIRECTION OUTPUT ;
    USE SIGNAL ;
    PORT
      LAYER M4 ;
        RECT 134.4500 780.8800 134.5500 781.4000 ;
    END
  END out0[124]
  PIN out0[123]
    DIRECTION OUTPUT ;
    USE SIGNAL ;
    PORT
      LAYER M4 ;
        RECT 136.4500 780.8800 136.5500 781.4000 ;
    END
  END out0[123]
  PIN out0[122]
    DIRECTION OUTPUT ;
    USE SIGNAL ;
    PORT
      LAYER M4 ;
        RECT 138.4500 780.8800 138.5500 781.4000 ;
    END
  END out0[122]
  PIN out0[121]
    DIRECTION OUTPUT ;
    USE SIGNAL ;
    PORT
      LAYER M4 ;
        RECT 140.4500 780.8800 140.5500 781.4000 ;
    END
  END out0[121]
  PIN out0[120]
    DIRECTION OUTPUT ;
    USE SIGNAL ;
    PORT
      LAYER M4 ;
        RECT 142.4500 780.8800 142.5500 781.4000 ;
    END
  END out0[120]
  PIN out0[119]
    DIRECTION OUTPUT ;
    USE SIGNAL ;
    PORT
      LAYER M4 ;
        RECT 144.4500 780.8800 144.5500 781.4000 ;
    END
  END out0[119]
  PIN out0[118]
    DIRECTION OUTPUT ;
    USE SIGNAL ;
    PORT
      LAYER M4 ;
        RECT 146.4500 780.8800 146.5500 781.4000 ;
    END
  END out0[118]
  PIN out0[117]
    DIRECTION OUTPUT ;
    USE SIGNAL ;
    PORT
      LAYER M4 ;
        RECT 148.4500 780.8800 148.5500 781.4000 ;
    END
  END out0[117]
  PIN out0[116]
    DIRECTION OUTPUT ;
    USE SIGNAL ;
    PORT
      LAYER M4 ;
        RECT 150.4500 780.8800 150.5500 781.4000 ;
    END
  END out0[116]
  PIN out0[115]
    DIRECTION OUTPUT ;
    USE SIGNAL ;
    PORT
      LAYER M4 ;
        RECT 152.4500 780.8800 152.5500 781.4000 ;
    END
  END out0[115]
  PIN out0[114]
    DIRECTION OUTPUT ;
    USE SIGNAL ;
    PORT
      LAYER M4 ;
        RECT 154.4500 780.8800 154.5500 781.4000 ;
    END
  END out0[114]
  PIN out0[113]
    DIRECTION OUTPUT ;
    USE SIGNAL ;
    PORT
      LAYER M4 ;
        RECT 156.4500 780.8800 156.5500 781.4000 ;
    END
  END out0[113]
  PIN out0[112]
    DIRECTION OUTPUT ;
    USE SIGNAL ;
    PORT
      LAYER M4 ;
        RECT 158.4500 780.8800 158.5500 781.4000 ;
    END
  END out0[112]
  PIN out0[111]
    DIRECTION OUTPUT ;
    USE SIGNAL ;
    PORT
      LAYER M4 ;
        RECT 160.4500 780.8800 160.5500 781.4000 ;
    END
  END out0[111]
  PIN out0[110]
    DIRECTION OUTPUT ;
    USE SIGNAL ;
    PORT
      LAYER M4 ;
        RECT 162.4500 780.8800 162.5500 781.4000 ;
    END
  END out0[110]
  PIN out0[109]
    DIRECTION OUTPUT ;
    USE SIGNAL ;
    PORT
      LAYER M4 ;
        RECT 164.4500 780.8800 164.5500 781.4000 ;
    END
  END out0[109]
  PIN out0[108]
    DIRECTION OUTPUT ;
    USE SIGNAL ;
    PORT
      LAYER M4 ;
        RECT 166.4500 780.8800 166.5500 781.4000 ;
    END
  END out0[108]
  PIN out0[107]
    DIRECTION OUTPUT ;
    USE SIGNAL ;
    PORT
      LAYER M4 ;
        RECT 168.4500 780.8800 168.5500 781.4000 ;
    END
  END out0[107]
  PIN out0[106]
    DIRECTION OUTPUT ;
    USE SIGNAL ;
    PORT
      LAYER M4 ;
        RECT 170.4500 780.8800 170.5500 781.4000 ;
    END
  END out0[106]
  PIN out0[105]
    DIRECTION OUTPUT ;
    USE SIGNAL ;
    PORT
      LAYER M4 ;
        RECT 172.4500 780.8800 172.5500 781.4000 ;
    END
  END out0[105]
  PIN out0[104]
    DIRECTION OUTPUT ;
    USE SIGNAL ;
    PORT
      LAYER M4 ;
        RECT 174.4500 780.8800 174.5500 781.4000 ;
    END
  END out0[104]
  PIN out0[103]
    DIRECTION OUTPUT ;
    USE SIGNAL ;
    PORT
      LAYER M4 ;
        RECT 176.4500 780.8800 176.5500 781.4000 ;
    END
  END out0[103]
  PIN out0[102]
    DIRECTION OUTPUT ;
    USE SIGNAL ;
    PORT
      LAYER M4 ;
        RECT 178.4500 780.8800 178.5500 781.4000 ;
    END
  END out0[102]
  PIN out0[101]
    DIRECTION OUTPUT ;
    USE SIGNAL ;
    PORT
      LAYER M4 ;
        RECT 180.4500 780.8800 180.5500 781.4000 ;
    END
  END out0[101]
  PIN out0[100]
    DIRECTION OUTPUT ;
    USE SIGNAL ;
    PORT
      LAYER M4 ;
        RECT 182.4500 780.8800 182.5500 781.4000 ;
    END
  END out0[100]
  PIN out0[99]
    DIRECTION OUTPUT ;
    USE SIGNAL ;
    PORT
      LAYER M4 ;
        RECT 184.4500 780.8800 184.5500 781.4000 ;
    END
  END out0[99]
  PIN out0[98]
    DIRECTION OUTPUT ;
    USE SIGNAL ;
    PORT
      LAYER M4 ;
        RECT 186.4500 780.8800 186.5500 781.4000 ;
    END
  END out0[98]
  PIN out0[97]
    DIRECTION OUTPUT ;
    USE SIGNAL ;
    PORT
      LAYER M4 ;
        RECT 188.4500 780.8800 188.5500 781.4000 ;
    END
  END out0[97]
  PIN out0[96]
    DIRECTION OUTPUT ;
    USE SIGNAL ;
    PORT
      LAYER M4 ;
        RECT 190.4500 780.8800 190.5500 781.4000 ;
    END
  END out0[96]
  PIN out0[95]
    DIRECTION OUTPUT ;
    USE SIGNAL ;
    PORT
      LAYER M4 ;
        RECT 192.4500 780.8800 192.5500 781.4000 ;
    END
  END out0[95]
  PIN out0[94]
    DIRECTION OUTPUT ;
    USE SIGNAL ;
    PORT
      LAYER M4 ;
        RECT 194.4500 780.8800 194.5500 781.4000 ;
    END
  END out0[94]
  PIN out0[93]
    DIRECTION OUTPUT ;
    USE SIGNAL ;
    PORT
      LAYER M4 ;
        RECT 196.4500 780.8800 196.5500 781.4000 ;
    END
  END out0[93]
  PIN out0[92]
    DIRECTION OUTPUT ;
    USE SIGNAL ;
    PORT
      LAYER M4 ;
        RECT 198.4500 780.8800 198.5500 781.4000 ;
    END
  END out0[92]
  PIN out0[91]
    DIRECTION OUTPUT ;
    USE SIGNAL ;
    PORT
      LAYER M4 ;
        RECT 200.4500 780.8800 200.5500 781.4000 ;
    END
  END out0[91]
  PIN out0[90]
    DIRECTION OUTPUT ;
    USE SIGNAL ;
    PORT
      LAYER M4 ;
        RECT 202.4500 780.8800 202.5500 781.4000 ;
    END
  END out0[90]
  PIN out0[89]
    DIRECTION OUTPUT ;
    USE SIGNAL ;
    PORT
      LAYER M4 ;
        RECT 204.4500 780.8800 204.5500 781.4000 ;
    END
  END out0[89]
  PIN out0[88]
    DIRECTION OUTPUT ;
    USE SIGNAL ;
    PORT
      LAYER M4 ;
        RECT 206.4500 780.8800 206.5500 781.4000 ;
    END
  END out0[88]
  PIN out0[87]
    DIRECTION OUTPUT ;
    USE SIGNAL ;
    PORT
      LAYER M4 ;
        RECT 208.4500 780.8800 208.5500 781.4000 ;
    END
  END out0[87]
  PIN out0[86]
    DIRECTION OUTPUT ;
    USE SIGNAL ;
    PORT
      LAYER M4 ;
        RECT 210.4500 780.8800 210.5500 781.4000 ;
    END
  END out0[86]
  PIN out0[85]
    DIRECTION OUTPUT ;
    USE SIGNAL ;
    PORT
      LAYER M4 ;
        RECT 212.4500 780.8800 212.5500 781.4000 ;
    END
  END out0[85]
  PIN out0[84]
    DIRECTION OUTPUT ;
    USE SIGNAL ;
    PORT
      LAYER M4 ;
        RECT 214.4500 780.8800 214.5500 781.4000 ;
    END
  END out0[84]
  PIN out0[83]
    DIRECTION OUTPUT ;
    USE SIGNAL ;
    PORT
      LAYER M4 ;
        RECT 216.4500 780.8800 216.5500 781.4000 ;
    END
  END out0[83]
  PIN out0[82]
    DIRECTION OUTPUT ;
    USE SIGNAL ;
    PORT
      LAYER M4 ;
        RECT 218.4500 780.8800 218.5500 781.4000 ;
    END
  END out0[82]
  PIN out0[81]
    DIRECTION OUTPUT ;
    USE SIGNAL ;
    PORT
      LAYER M4 ;
        RECT 220.4500 780.8800 220.5500 781.4000 ;
    END
  END out0[81]
  PIN out0[80]
    DIRECTION OUTPUT ;
    USE SIGNAL ;
    PORT
      LAYER M4 ;
        RECT 222.4500 780.8800 222.5500 781.4000 ;
    END
  END out0[80]
  PIN out0[79]
    DIRECTION OUTPUT ;
    USE SIGNAL ;
    PORT
      LAYER M4 ;
        RECT 224.4500 780.8800 224.5500 781.4000 ;
    END
  END out0[79]
  PIN out0[78]
    DIRECTION OUTPUT ;
    USE SIGNAL ;
    PORT
      LAYER M4 ;
        RECT 226.4500 780.8800 226.5500 781.4000 ;
    END
  END out0[78]
  PIN out0[77]
    DIRECTION OUTPUT ;
    USE SIGNAL ;
    PORT
      LAYER M4 ;
        RECT 228.4500 780.8800 228.5500 781.4000 ;
    END
  END out0[77]
  PIN out0[76]
    DIRECTION OUTPUT ;
    USE SIGNAL ;
    PORT
      LAYER M4 ;
        RECT 230.4500 780.8800 230.5500 781.4000 ;
    END
  END out0[76]
  PIN out0[75]
    DIRECTION OUTPUT ;
    USE SIGNAL ;
    PORT
      LAYER M4 ;
        RECT 232.4500 780.8800 232.5500 781.4000 ;
    END
  END out0[75]
  PIN out0[74]
    DIRECTION OUTPUT ;
    USE SIGNAL ;
    PORT
      LAYER M4 ;
        RECT 234.4500 780.8800 234.5500 781.4000 ;
    END
  END out0[74]
  PIN out0[73]
    DIRECTION OUTPUT ;
    USE SIGNAL ;
    PORT
      LAYER M4 ;
        RECT 236.4500 780.8800 236.5500 781.4000 ;
    END
  END out0[73]
  PIN out0[72]
    DIRECTION OUTPUT ;
    USE SIGNAL ;
    PORT
      LAYER M4 ;
        RECT 238.4500 780.8800 238.5500 781.4000 ;
    END
  END out0[72]
  PIN out0[71]
    DIRECTION OUTPUT ;
    USE SIGNAL ;
    PORT
      LAYER M4 ;
        RECT 240.4500 780.8800 240.5500 781.4000 ;
    END
  END out0[71]
  PIN out0[70]
    DIRECTION OUTPUT ;
    USE SIGNAL ;
    PORT
      LAYER M4 ;
        RECT 242.4500 780.8800 242.5500 781.4000 ;
    END
  END out0[70]
  PIN out0[69]
    DIRECTION OUTPUT ;
    USE SIGNAL ;
    PORT
      LAYER M4 ;
        RECT 244.4500 780.8800 244.5500 781.4000 ;
    END
  END out0[69]
  PIN out0[68]
    DIRECTION OUTPUT ;
    USE SIGNAL ;
    PORT
      LAYER M4 ;
        RECT 246.4500 780.8800 246.5500 781.4000 ;
    END
  END out0[68]
  PIN out0[67]
    DIRECTION OUTPUT ;
    USE SIGNAL ;
    PORT
      LAYER M4 ;
        RECT 248.4500 780.8800 248.5500 781.4000 ;
    END
  END out0[67]
  PIN out0[66]
    DIRECTION OUTPUT ;
    USE SIGNAL ;
    PORT
      LAYER M4 ;
        RECT 250.4500 780.8800 250.5500 781.4000 ;
    END
  END out0[66]
  PIN out0[65]
    DIRECTION OUTPUT ;
    USE SIGNAL ;
    PORT
      LAYER M4 ;
        RECT 252.4500 780.8800 252.5500 781.4000 ;
    END
  END out0[65]
  PIN out0[64]
    DIRECTION OUTPUT ;
    USE SIGNAL ;
    PORT
      LAYER M4 ;
        RECT 254.4500 780.8800 254.5500 781.4000 ;
    END
  END out0[64]
  PIN out0[63]
    DIRECTION OUTPUT ;
    USE SIGNAL ;
    PORT
      LAYER M4 ;
        RECT 256.4500 780.8800 256.5500 781.4000 ;
    END
  END out0[63]
  PIN out0[62]
    DIRECTION OUTPUT ;
    USE SIGNAL ;
    PORT
      LAYER M4 ;
        RECT 258.4500 780.8800 258.5500 781.4000 ;
    END
  END out0[62]
  PIN out0[61]
    DIRECTION OUTPUT ;
    USE SIGNAL ;
    PORT
      LAYER M4 ;
        RECT 260.4500 780.8800 260.5500 781.4000 ;
    END
  END out0[61]
  PIN out0[60]
    DIRECTION OUTPUT ;
    USE SIGNAL ;
    PORT
      LAYER M4 ;
        RECT 262.4500 780.8800 262.5500 781.4000 ;
    END
  END out0[60]
  PIN out0[59]
    DIRECTION OUTPUT ;
    USE SIGNAL ;
    PORT
      LAYER M4 ;
        RECT 264.4500 780.8800 264.5500 781.4000 ;
    END
  END out0[59]
  PIN out0[58]
    DIRECTION OUTPUT ;
    USE SIGNAL ;
    PORT
      LAYER M4 ;
        RECT 266.4500 780.8800 266.5500 781.4000 ;
    END
  END out0[58]
  PIN out0[57]
    DIRECTION OUTPUT ;
    USE SIGNAL ;
    PORT
      LAYER M4 ;
        RECT 268.4500 780.8800 268.5500 781.4000 ;
    END
  END out0[57]
  PIN out0[56]
    DIRECTION OUTPUT ;
    USE SIGNAL ;
    PORT
      LAYER M4 ;
        RECT 270.4500 780.8800 270.5500 781.4000 ;
    END
  END out0[56]
  PIN out0[55]
    DIRECTION OUTPUT ;
    USE SIGNAL ;
    PORT
      LAYER M4 ;
        RECT 272.4500 780.8800 272.5500 781.4000 ;
    END
  END out0[55]
  PIN out0[54]
    DIRECTION OUTPUT ;
    USE SIGNAL ;
    PORT
      LAYER M4 ;
        RECT 274.4500 780.8800 274.5500 781.4000 ;
    END
  END out0[54]
  PIN out0[53]
    DIRECTION OUTPUT ;
    USE SIGNAL ;
    PORT
      LAYER M4 ;
        RECT 276.4500 780.8800 276.5500 781.4000 ;
    END
  END out0[53]
  PIN out0[52]
    DIRECTION OUTPUT ;
    USE SIGNAL ;
    PORT
      LAYER M4 ;
        RECT 278.4500 780.8800 278.5500 781.4000 ;
    END
  END out0[52]
  PIN out0[51]
    DIRECTION OUTPUT ;
    USE SIGNAL ;
    PORT
      LAYER M4 ;
        RECT 280.4500 780.8800 280.5500 781.4000 ;
    END
  END out0[51]
  PIN out0[50]
    DIRECTION OUTPUT ;
    USE SIGNAL ;
    PORT
      LAYER M4 ;
        RECT 282.4500 780.8800 282.5500 781.4000 ;
    END
  END out0[50]
  PIN out0[49]
    DIRECTION OUTPUT ;
    USE SIGNAL ;
    PORT
      LAYER M4 ;
        RECT 284.4500 780.8800 284.5500 781.4000 ;
    END
  END out0[49]
  PIN out0[48]
    DIRECTION OUTPUT ;
    USE SIGNAL ;
    PORT
      LAYER M4 ;
        RECT 286.4500 780.8800 286.5500 781.4000 ;
    END
  END out0[48]
  PIN out0[47]
    DIRECTION OUTPUT ;
    USE SIGNAL ;
    PORT
      LAYER M4 ;
        RECT 288.4500 780.8800 288.5500 781.4000 ;
    END
  END out0[47]
  PIN out0[46]
    DIRECTION OUTPUT ;
    USE SIGNAL ;
    PORT
      LAYER M4 ;
        RECT 290.4500 780.8800 290.5500 781.4000 ;
    END
  END out0[46]
  PIN out0[45]
    DIRECTION OUTPUT ;
    USE SIGNAL ;
    PORT
      LAYER M4 ;
        RECT 292.4500 780.8800 292.5500 781.4000 ;
    END
  END out0[45]
  PIN out0[44]
    DIRECTION OUTPUT ;
    USE SIGNAL ;
    PORT
      LAYER M4 ;
        RECT 294.4500 780.8800 294.5500 781.4000 ;
    END
  END out0[44]
  PIN out0[43]
    DIRECTION OUTPUT ;
    USE SIGNAL ;
    PORT
      LAYER M4 ;
        RECT 296.4500 780.8800 296.5500 781.4000 ;
    END
  END out0[43]
  PIN out0[42]
    DIRECTION OUTPUT ;
    USE SIGNAL ;
    PORT
      LAYER M4 ;
        RECT 298.4500 780.8800 298.5500 781.4000 ;
    END
  END out0[42]
  PIN out0[41]
    DIRECTION OUTPUT ;
    USE SIGNAL ;
    PORT
      LAYER M4 ;
        RECT 300.4500 780.8800 300.5500 781.4000 ;
    END
  END out0[41]
  PIN out0[40]
    DIRECTION OUTPUT ;
    USE SIGNAL ;
    PORT
      LAYER M4 ;
        RECT 302.4500 780.8800 302.5500 781.4000 ;
    END
  END out0[40]
  PIN out0[39]
    DIRECTION OUTPUT ;
    USE SIGNAL ;
    PORT
      LAYER M4 ;
        RECT 304.4500 780.8800 304.5500 781.4000 ;
    END
  END out0[39]
  PIN out0[38]
    DIRECTION OUTPUT ;
    USE SIGNAL ;
    PORT
      LAYER M4 ;
        RECT 306.4500 780.8800 306.5500 781.4000 ;
    END
  END out0[38]
  PIN out0[37]
    DIRECTION OUTPUT ;
    USE SIGNAL ;
    PORT
      LAYER M4 ;
        RECT 308.4500 780.8800 308.5500 781.4000 ;
    END
  END out0[37]
  PIN out0[36]
    DIRECTION OUTPUT ;
    USE SIGNAL ;
    PORT
      LAYER M4 ;
        RECT 310.4500 780.8800 310.5500 781.4000 ;
    END
  END out0[36]
  PIN out0[35]
    DIRECTION OUTPUT ;
    USE SIGNAL ;
    PORT
      LAYER M4 ;
        RECT 312.4500 780.8800 312.5500 781.4000 ;
    END
  END out0[35]
  PIN out0[34]
    DIRECTION OUTPUT ;
    USE SIGNAL ;
    PORT
      LAYER M4 ;
        RECT 314.4500 780.8800 314.5500 781.4000 ;
    END
  END out0[34]
  PIN out0[33]
    DIRECTION OUTPUT ;
    USE SIGNAL ;
    PORT
      LAYER M4 ;
        RECT 316.4500 780.8800 316.5500 781.4000 ;
    END
  END out0[33]
  PIN out0[32]
    DIRECTION OUTPUT ;
    USE SIGNAL ;
    PORT
      LAYER M4 ;
        RECT 318.4500 780.8800 318.5500 781.4000 ;
    END
  END out0[32]
  PIN out0[31]
    DIRECTION OUTPUT ;
    USE SIGNAL ;
    PORT
      LAYER M4 ;
        RECT 320.4500 780.8800 320.5500 781.4000 ;
    END
  END out0[31]
  PIN out0[30]
    DIRECTION OUTPUT ;
    USE SIGNAL ;
    PORT
      LAYER M4 ;
        RECT 322.4500 780.8800 322.5500 781.4000 ;
    END
  END out0[30]
  PIN out0[29]
    DIRECTION OUTPUT ;
    USE SIGNAL ;
    PORT
      LAYER M4 ;
        RECT 324.4500 780.8800 324.5500 781.4000 ;
    END
  END out0[29]
  PIN out0[28]
    DIRECTION OUTPUT ;
    USE SIGNAL ;
    PORT
      LAYER M4 ;
        RECT 326.4500 780.8800 326.5500 781.4000 ;
    END
  END out0[28]
  PIN out0[27]
    DIRECTION OUTPUT ;
    USE SIGNAL ;
    PORT
      LAYER M4 ;
        RECT 328.4500 780.8800 328.5500 781.4000 ;
    END
  END out0[27]
  PIN out0[26]
    DIRECTION OUTPUT ;
    USE SIGNAL ;
    PORT
      LAYER M4 ;
        RECT 330.4500 780.8800 330.5500 781.4000 ;
    END
  END out0[26]
  PIN out0[25]
    DIRECTION OUTPUT ;
    USE SIGNAL ;
    PORT
      LAYER M4 ;
        RECT 332.4500 780.8800 332.5500 781.4000 ;
    END
  END out0[25]
  PIN out0[24]
    DIRECTION OUTPUT ;
    USE SIGNAL ;
    PORT
      LAYER M4 ;
        RECT 334.4500 780.8800 334.5500 781.4000 ;
    END
  END out0[24]
  PIN out0[23]
    DIRECTION OUTPUT ;
    USE SIGNAL ;
    PORT
      LAYER M4 ;
        RECT 336.4500 780.8800 336.5500 781.4000 ;
    END
  END out0[23]
  PIN out0[22]
    DIRECTION OUTPUT ;
    USE SIGNAL ;
    PORT
      LAYER M4 ;
        RECT 338.4500 780.8800 338.5500 781.4000 ;
    END
  END out0[22]
  PIN out0[21]
    DIRECTION OUTPUT ;
    USE SIGNAL ;
    PORT
      LAYER M4 ;
        RECT 340.4500 780.8800 340.5500 781.4000 ;
    END
  END out0[21]
  PIN out0[20]
    DIRECTION OUTPUT ;
    USE SIGNAL ;
    PORT
      LAYER M4 ;
        RECT 342.4500 780.8800 342.5500 781.4000 ;
    END
  END out0[20]
  PIN out0[19]
    DIRECTION OUTPUT ;
    USE SIGNAL ;
    PORT
      LAYER M4 ;
        RECT 344.4500 780.8800 344.5500 781.4000 ;
    END
  END out0[19]
  PIN out0[18]
    DIRECTION OUTPUT ;
    USE SIGNAL ;
    PORT
      LAYER M4 ;
        RECT 346.4500 780.8800 346.5500 781.4000 ;
    END
  END out0[18]
  PIN out0[17]
    DIRECTION OUTPUT ;
    USE SIGNAL ;
    PORT
      LAYER M4 ;
        RECT 348.4500 780.8800 348.5500 781.4000 ;
    END
  END out0[17]
  PIN out0[16]
    DIRECTION OUTPUT ;
    USE SIGNAL ;
    PORT
      LAYER M4 ;
        RECT 350.4500 780.8800 350.5500 781.4000 ;
    END
  END out0[16]
  PIN out0[15]
    DIRECTION OUTPUT ;
    USE SIGNAL ;
    PORT
      LAYER M4 ;
        RECT 352.4500 780.8800 352.5500 781.4000 ;
    END
  END out0[15]
  PIN out0[14]
    DIRECTION OUTPUT ;
    USE SIGNAL ;
    PORT
      LAYER M4 ;
        RECT 354.4500 780.8800 354.5500 781.4000 ;
    END
  END out0[14]
  PIN out0[13]
    DIRECTION OUTPUT ;
    USE SIGNAL ;
    PORT
      LAYER M4 ;
        RECT 356.4500 780.8800 356.5500 781.4000 ;
    END
  END out0[13]
  PIN out0[12]
    DIRECTION OUTPUT ;
    USE SIGNAL ;
    PORT
      LAYER M4 ;
        RECT 358.4500 780.8800 358.5500 781.4000 ;
    END
  END out0[12]
  PIN out0[11]
    DIRECTION OUTPUT ;
    USE SIGNAL ;
    PORT
      LAYER M4 ;
        RECT 360.4500 780.8800 360.5500 781.4000 ;
    END
  END out0[11]
  PIN out0[10]
    DIRECTION OUTPUT ;
    USE SIGNAL ;
    PORT
      LAYER M4 ;
        RECT 362.4500 780.8800 362.5500 781.4000 ;
    END
  END out0[10]
  PIN out0[9]
    DIRECTION OUTPUT ;
    USE SIGNAL ;
    PORT
      LAYER M4 ;
        RECT 364.4500 780.8800 364.5500 781.4000 ;
    END
  END out0[9]
  PIN out0[8]
    DIRECTION OUTPUT ;
    USE SIGNAL ;
    PORT
      LAYER M4 ;
        RECT 366.4500 780.8800 366.5500 781.4000 ;
    END
  END out0[8]
  PIN out0[7]
    DIRECTION OUTPUT ;
    USE SIGNAL ;
    PORT
      LAYER M4 ;
        RECT 368.4500 780.8800 368.5500 781.4000 ;
    END
  END out0[7]
  PIN out0[6]
    DIRECTION OUTPUT ;
    USE SIGNAL ;
    PORT
      LAYER M4 ;
        RECT 370.4500 780.8800 370.5500 781.4000 ;
    END
  END out0[6]
  PIN out0[5]
    DIRECTION OUTPUT ;
    USE SIGNAL ;
    PORT
      LAYER M4 ;
        RECT 372.4500 780.8800 372.5500 781.4000 ;
    END
  END out0[5]
  PIN out0[4]
    DIRECTION OUTPUT ;
    USE SIGNAL ;
    PORT
      LAYER M4 ;
        RECT 374.4500 780.8800 374.5500 781.4000 ;
    END
  END out0[4]
  PIN out0[3]
    DIRECTION OUTPUT ;
    USE SIGNAL ;
    PORT
      LAYER M4 ;
        RECT 376.4500 780.8800 376.5500 781.4000 ;
    END
  END out0[3]
  PIN out0[2]
    DIRECTION OUTPUT ;
    USE SIGNAL ;
    PORT
      LAYER M4 ;
        RECT 378.4500 780.8800 378.5500 781.4000 ;
    END
  END out0[2]
  PIN out0[1]
    DIRECTION OUTPUT ;
    USE SIGNAL ;
    PORT
      LAYER M4 ;
        RECT 380.4500 780.8800 380.5500 781.4000 ;
    END
  END out0[1]
  PIN out0[0]
    DIRECTION OUTPUT ;
    USE SIGNAL ;
    PORT
      LAYER M4 ;
        RECT 382.4500 780.8800 382.5500 781.4000 ;
    END
  END out0[0]
  PIN out1[159]
    DIRECTION OUTPUT ;
    USE SIGNAL ;
    PORT
      LAYER M4 ;
        RECT 384.4500 780.8800 384.5500 781.4000 ;
    END
  END out1[159]
  PIN out1[158]
    DIRECTION OUTPUT ;
    USE SIGNAL ;
    PORT
      LAYER M4 ;
        RECT 386.4500 780.8800 386.5500 781.4000 ;
    END
  END out1[158]
  PIN out1[157]
    DIRECTION OUTPUT ;
    USE SIGNAL ;
    PORT
      LAYER M4 ;
        RECT 388.4500 780.8800 388.5500 781.4000 ;
    END
  END out1[157]
  PIN out1[156]
    DIRECTION OUTPUT ;
    USE SIGNAL ;
    PORT
      LAYER M4 ;
        RECT 390.4500 780.8800 390.5500 781.4000 ;
    END
  END out1[156]
  PIN out1[155]
    DIRECTION OUTPUT ;
    USE SIGNAL ;
    PORT
      LAYER M4 ;
        RECT 392.4500 780.8800 392.5500 781.4000 ;
    END
  END out1[155]
  PIN out1[154]
    DIRECTION OUTPUT ;
    USE SIGNAL ;
    PORT
      LAYER M4 ;
        RECT 394.4500 780.8800 394.5500 781.4000 ;
    END
  END out1[154]
  PIN out1[153]
    DIRECTION OUTPUT ;
    USE SIGNAL ;
    PORT
      LAYER M4 ;
        RECT 396.4500 780.8800 396.5500 781.4000 ;
    END
  END out1[153]
  PIN out1[152]
    DIRECTION OUTPUT ;
    USE SIGNAL ;
    PORT
      LAYER M4 ;
        RECT 398.4500 780.8800 398.5500 781.4000 ;
    END
  END out1[152]
  PIN out1[151]
    DIRECTION OUTPUT ;
    USE SIGNAL ;
    PORT
      LAYER M4 ;
        RECT 400.4500 780.8800 400.5500 781.4000 ;
    END
  END out1[151]
  PIN out1[150]
    DIRECTION OUTPUT ;
    USE SIGNAL ;
    PORT
      LAYER M4 ;
        RECT 402.4500 780.8800 402.5500 781.4000 ;
    END
  END out1[150]
  PIN out1[149]
    DIRECTION OUTPUT ;
    USE SIGNAL ;
    PORT
      LAYER M4 ;
        RECT 404.4500 780.8800 404.5500 781.4000 ;
    END
  END out1[149]
  PIN out1[148]
    DIRECTION OUTPUT ;
    USE SIGNAL ;
    PORT
      LAYER M4 ;
        RECT 406.4500 780.8800 406.5500 781.4000 ;
    END
  END out1[148]
  PIN out1[147]
    DIRECTION OUTPUT ;
    USE SIGNAL ;
    PORT
      LAYER M4 ;
        RECT 408.4500 780.8800 408.5500 781.4000 ;
    END
  END out1[147]
  PIN out1[146]
    DIRECTION OUTPUT ;
    USE SIGNAL ;
    PORT
      LAYER M4 ;
        RECT 410.4500 780.8800 410.5500 781.4000 ;
    END
  END out1[146]
  PIN out1[145]
    DIRECTION OUTPUT ;
    USE SIGNAL ;
    PORT
      LAYER M4 ;
        RECT 412.4500 780.8800 412.5500 781.4000 ;
    END
  END out1[145]
  PIN out1[144]
    DIRECTION OUTPUT ;
    USE SIGNAL ;
    PORT
      LAYER M4 ;
        RECT 414.4500 780.8800 414.5500 781.4000 ;
    END
  END out1[144]
  PIN out1[143]
    DIRECTION OUTPUT ;
    USE SIGNAL ;
    PORT
      LAYER M4 ;
        RECT 416.4500 780.8800 416.5500 781.4000 ;
    END
  END out1[143]
  PIN out1[142]
    DIRECTION OUTPUT ;
    USE SIGNAL ;
    PORT
      LAYER M4 ;
        RECT 418.4500 780.8800 418.5500 781.4000 ;
    END
  END out1[142]
  PIN out1[141]
    DIRECTION OUTPUT ;
    USE SIGNAL ;
    PORT
      LAYER M4 ;
        RECT 420.4500 780.8800 420.5500 781.4000 ;
    END
  END out1[141]
  PIN out1[140]
    DIRECTION OUTPUT ;
    USE SIGNAL ;
    PORT
      LAYER M4 ;
        RECT 422.4500 780.8800 422.5500 781.4000 ;
    END
  END out1[140]
  PIN out1[139]
    DIRECTION OUTPUT ;
    USE SIGNAL ;
    PORT
      LAYER M4 ;
        RECT 424.4500 780.8800 424.5500 781.4000 ;
    END
  END out1[139]
  PIN out1[138]
    DIRECTION OUTPUT ;
    USE SIGNAL ;
    PORT
      LAYER M4 ;
        RECT 426.4500 780.8800 426.5500 781.4000 ;
    END
  END out1[138]
  PIN out1[137]
    DIRECTION OUTPUT ;
    USE SIGNAL ;
    PORT
      LAYER M4 ;
        RECT 428.4500 780.8800 428.5500 781.4000 ;
    END
  END out1[137]
  PIN out1[136]
    DIRECTION OUTPUT ;
    USE SIGNAL ;
    PORT
      LAYER M4 ;
        RECT 430.4500 780.8800 430.5500 781.4000 ;
    END
  END out1[136]
  PIN out1[135]
    DIRECTION OUTPUT ;
    USE SIGNAL ;
    PORT
      LAYER M4 ;
        RECT 432.4500 780.8800 432.5500 781.4000 ;
    END
  END out1[135]
  PIN out1[134]
    DIRECTION OUTPUT ;
    USE SIGNAL ;
    PORT
      LAYER M4 ;
        RECT 434.4500 780.8800 434.5500 781.4000 ;
    END
  END out1[134]
  PIN out1[133]
    DIRECTION OUTPUT ;
    USE SIGNAL ;
    PORT
      LAYER M4 ;
        RECT 436.4500 780.8800 436.5500 781.4000 ;
    END
  END out1[133]
  PIN out1[132]
    DIRECTION OUTPUT ;
    USE SIGNAL ;
    PORT
      LAYER M4 ;
        RECT 438.4500 780.8800 438.5500 781.4000 ;
    END
  END out1[132]
  PIN out1[131]
    DIRECTION OUTPUT ;
    USE SIGNAL ;
    PORT
      LAYER M4 ;
        RECT 440.4500 780.8800 440.5500 781.4000 ;
    END
  END out1[131]
  PIN out1[130]
    DIRECTION OUTPUT ;
    USE SIGNAL ;
    PORT
      LAYER M4 ;
        RECT 442.4500 780.8800 442.5500 781.4000 ;
    END
  END out1[130]
  PIN out1[129]
    DIRECTION OUTPUT ;
    USE SIGNAL ;
    PORT
      LAYER M4 ;
        RECT 444.4500 780.8800 444.5500 781.4000 ;
    END
  END out1[129]
  PIN out1[128]
    DIRECTION OUTPUT ;
    USE SIGNAL ;
    PORT
      LAYER M4 ;
        RECT 446.4500 780.8800 446.5500 781.4000 ;
    END
  END out1[128]
  PIN out1[127]
    DIRECTION OUTPUT ;
    USE SIGNAL ;
    PORT
      LAYER M4 ;
        RECT 448.4500 780.8800 448.5500 781.4000 ;
    END
  END out1[127]
  PIN out1[126]
    DIRECTION OUTPUT ;
    USE SIGNAL ;
    PORT
      LAYER M4 ;
        RECT 450.4500 780.8800 450.5500 781.4000 ;
    END
  END out1[126]
  PIN out1[125]
    DIRECTION OUTPUT ;
    USE SIGNAL ;
    PORT
      LAYER M4 ;
        RECT 452.4500 780.8800 452.5500 781.4000 ;
    END
  END out1[125]
  PIN out1[124]
    DIRECTION OUTPUT ;
    USE SIGNAL ;
    PORT
      LAYER M4 ;
        RECT 454.4500 780.8800 454.5500 781.4000 ;
    END
  END out1[124]
  PIN out1[123]
    DIRECTION OUTPUT ;
    USE SIGNAL ;
    PORT
      LAYER M4 ;
        RECT 456.4500 780.8800 456.5500 781.4000 ;
    END
  END out1[123]
  PIN out1[122]
    DIRECTION OUTPUT ;
    USE SIGNAL ;
    PORT
      LAYER M4 ;
        RECT 458.4500 780.8800 458.5500 781.4000 ;
    END
  END out1[122]
  PIN out1[121]
    DIRECTION OUTPUT ;
    USE SIGNAL ;
    PORT
      LAYER M4 ;
        RECT 460.4500 780.8800 460.5500 781.4000 ;
    END
  END out1[121]
  PIN out1[120]
    DIRECTION OUTPUT ;
    USE SIGNAL ;
    PORT
      LAYER M4 ;
        RECT 462.4500 780.8800 462.5500 781.4000 ;
    END
  END out1[120]
  PIN out1[119]
    DIRECTION OUTPUT ;
    USE SIGNAL ;
    PORT
      LAYER M4 ;
        RECT 464.4500 780.8800 464.5500 781.4000 ;
    END
  END out1[119]
  PIN out1[118]
    DIRECTION OUTPUT ;
    USE SIGNAL ;
    PORT
      LAYER M4 ;
        RECT 466.4500 780.8800 466.5500 781.4000 ;
    END
  END out1[118]
  PIN out1[117]
    DIRECTION OUTPUT ;
    USE SIGNAL ;
    PORT
      LAYER M4 ;
        RECT 468.4500 780.8800 468.5500 781.4000 ;
    END
  END out1[117]
  PIN out1[116]
    DIRECTION OUTPUT ;
    USE SIGNAL ;
    PORT
      LAYER M4 ;
        RECT 470.4500 780.8800 470.5500 781.4000 ;
    END
  END out1[116]
  PIN out1[115]
    DIRECTION OUTPUT ;
    USE SIGNAL ;
    PORT
      LAYER M4 ;
        RECT 472.4500 780.8800 472.5500 781.4000 ;
    END
  END out1[115]
  PIN out1[114]
    DIRECTION OUTPUT ;
    USE SIGNAL ;
    PORT
      LAYER M4 ;
        RECT 474.4500 780.8800 474.5500 781.4000 ;
    END
  END out1[114]
  PIN out1[113]
    DIRECTION OUTPUT ;
    USE SIGNAL ;
    PORT
      LAYER M4 ;
        RECT 476.4500 780.8800 476.5500 781.4000 ;
    END
  END out1[113]
  PIN out1[112]
    DIRECTION OUTPUT ;
    USE SIGNAL ;
    PORT
      LAYER M4 ;
        RECT 478.4500 780.8800 478.5500 781.4000 ;
    END
  END out1[112]
  PIN out1[111]
    DIRECTION OUTPUT ;
    USE SIGNAL ;
    PORT
      LAYER M4 ;
        RECT 480.4500 780.8800 480.5500 781.4000 ;
    END
  END out1[111]
  PIN out1[110]
    DIRECTION OUTPUT ;
    USE SIGNAL ;
    PORT
      LAYER M4 ;
        RECT 482.4500 780.8800 482.5500 781.4000 ;
    END
  END out1[110]
  PIN out1[109]
    DIRECTION OUTPUT ;
    USE SIGNAL ;
    PORT
      LAYER M4 ;
        RECT 484.4500 780.8800 484.5500 781.4000 ;
    END
  END out1[109]
  PIN out1[108]
    DIRECTION OUTPUT ;
    USE SIGNAL ;
    PORT
      LAYER M4 ;
        RECT 486.4500 780.8800 486.5500 781.4000 ;
    END
  END out1[108]
  PIN out1[107]
    DIRECTION OUTPUT ;
    USE SIGNAL ;
    PORT
      LAYER M4 ;
        RECT 488.4500 780.8800 488.5500 781.4000 ;
    END
  END out1[107]
  PIN out1[106]
    DIRECTION OUTPUT ;
    USE SIGNAL ;
    PORT
      LAYER M4 ;
        RECT 490.4500 780.8800 490.5500 781.4000 ;
    END
  END out1[106]
  PIN out1[105]
    DIRECTION OUTPUT ;
    USE SIGNAL ;
    PORT
      LAYER M4 ;
        RECT 492.4500 780.8800 492.5500 781.4000 ;
    END
  END out1[105]
  PIN out1[104]
    DIRECTION OUTPUT ;
    USE SIGNAL ;
    PORT
      LAYER M4 ;
        RECT 494.4500 780.8800 494.5500 781.4000 ;
    END
  END out1[104]
  PIN out1[103]
    DIRECTION OUTPUT ;
    USE SIGNAL ;
    PORT
      LAYER M4 ;
        RECT 496.4500 780.8800 496.5500 781.4000 ;
    END
  END out1[103]
  PIN out1[102]
    DIRECTION OUTPUT ;
    USE SIGNAL ;
    PORT
      LAYER M4 ;
        RECT 498.4500 780.8800 498.5500 781.4000 ;
    END
  END out1[102]
  PIN out1[101]
    DIRECTION OUTPUT ;
    USE SIGNAL ;
    PORT
      LAYER M4 ;
        RECT 500.4500 780.8800 500.5500 781.4000 ;
    END
  END out1[101]
  PIN out1[100]
    DIRECTION OUTPUT ;
    USE SIGNAL ;
    PORT
      LAYER M4 ;
        RECT 502.4500 780.8800 502.5500 781.4000 ;
    END
  END out1[100]
  PIN out1[99]
    DIRECTION OUTPUT ;
    USE SIGNAL ;
    PORT
      LAYER M4 ;
        RECT 504.4500 780.8800 504.5500 781.4000 ;
    END
  END out1[99]
  PIN out1[98]
    DIRECTION OUTPUT ;
    USE SIGNAL ;
    PORT
      LAYER M4 ;
        RECT 506.4500 780.8800 506.5500 781.4000 ;
    END
  END out1[98]
  PIN out1[97]
    DIRECTION OUTPUT ;
    USE SIGNAL ;
    PORT
      LAYER M4 ;
        RECT 508.4500 780.8800 508.5500 781.4000 ;
    END
  END out1[97]
  PIN out1[96]
    DIRECTION OUTPUT ;
    USE SIGNAL ;
    PORT
      LAYER M4 ;
        RECT 510.4500 780.8800 510.5500 781.4000 ;
    END
  END out1[96]
  PIN out1[95]
    DIRECTION OUTPUT ;
    USE SIGNAL ;
    PORT
      LAYER M4 ;
        RECT 512.4500 780.8800 512.5500 781.4000 ;
    END
  END out1[95]
  PIN out1[94]
    DIRECTION OUTPUT ;
    USE SIGNAL ;
    PORT
      LAYER M4 ;
        RECT 514.4500 780.8800 514.5500 781.4000 ;
    END
  END out1[94]
  PIN out1[93]
    DIRECTION OUTPUT ;
    USE SIGNAL ;
    PORT
      LAYER M4 ;
        RECT 516.4500 780.8800 516.5500 781.4000 ;
    END
  END out1[93]
  PIN out1[92]
    DIRECTION OUTPUT ;
    USE SIGNAL ;
    PORT
      LAYER M4 ;
        RECT 518.4500 780.8800 518.5500 781.4000 ;
    END
  END out1[92]
  PIN out1[91]
    DIRECTION OUTPUT ;
    USE SIGNAL ;
    PORT
      LAYER M4 ;
        RECT 520.4500 780.8800 520.5500 781.4000 ;
    END
  END out1[91]
  PIN out1[90]
    DIRECTION OUTPUT ;
    USE SIGNAL ;
    PORT
      LAYER M4 ;
        RECT 522.4500 780.8800 522.5500 781.4000 ;
    END
  END out1[90]
  PIN out1[89]
    DIRECTION OUTPUT ;
    USE SIGNAL ;
    PORT
      LAYER M4 ;
        RECT 524.4500 780.8800 524.5500 781.4000 ;
    END
  END out1[89]
  PIN out1[88]
    DIRECTION OUTPUT ;
    USE SIGNAL ;
    PORT
      LAYER M4 ;
        RECT 526.4500 780.8800 526.5500 781.4000 ;
    END
  END out1[88]
  PIN out1[87]
    DIRECTION OUTPUT ;
    USE SIGNAL ;
    PORT
      LAYER M4 ;
        RECT 528.4500 780.8800 528.5500 781.4000 ;
    END
  END out1[87]
  PIN out1[86]
    DIRECTION OUTPUT ;
    USE SIGNAL ;
    PORT
      LAYER M4 ;
        RECT 530.4500 780.8800 530.5500 781.4000 ;
    END
  END out1[86]
  PIN out1[85]
    DIRECTION OUTPUT ;
    USE SIGNAL ;
    PORT
      LAYER M4 ;
        RECT 532.4500 780.8800 532.5500 781.4000 ;
    END
  END out1[85]
  PIN out1[84]
    DIRECTION OUTPUT ;
    USE SIGNAL ;
    PORT
      LAYER M4 ;
        RECT 534.4500 780.8800 534.5500 781.4000 ;
    END
  END out1[84]
  PIN out1[83]
    DIRECTION OUTPUT ;
    USE SIGNAL ;
    PORT
      LAYER M4 ;
        RECT 536.4500 780.8800 536.5500 781.4000 ;
    END
  END out1[83]
  PIN out1[82]
    DIRECTION OUTPUT ;
    USE SIGNAL ;
    PORT
      LAYER M4 ;
        RECT 538.4500 780.8800 538.5500 781.4000 ;
    END
  END out1[82]
  PIN out1[81]
    DIRECTION OUTPUT ;
    USE SIGNAL ;
    PORT
      LAYER M4 ;
        RECT 540.4500 780.8800 540.5500 781.4000 ;
    END
  END out1[81]
  PIN out1[80]
    DIRECTION OUTPUT ;
    USE SIGNAL ;
    PORT
      LAYER M4 ;
        RECT 542.4500 780.8800 542.5500 781.4000 ;
    END
  END out1[80]
  PIN out1[79]
    DIRECTION OUTPUT ;
    USE SIGNAL ;
    PORT
      LAYER M4 ;
        RECT 544.4500 780.8800 544.5500 781.4000 ;
    END
  END out1[79]
  PIN out1[78]
    DIRECTION OUTPUT ;
    USE SIGNAL ;
    PORT
      LAYER M4 ;
        RECT 546.4500 780.8800 546.5500 781.4000 ;
    END
  END out1[78]
  PIN out1[77]
    DIRECTION OUTPUT ;
    USE SIGNAL ;
    PORT
      LAYER M4 ;
        RECT 548.4500 780.8800 548.5500 781.4000 ;
    END
  END out1[77]
  PIN out1[76]
    DIRECTION OUTPUT ;
    USE SIGNAL ;
    PORT
      LAYER M4 ;
        RECT 550.4500 780.8800 550.5500 781.4000 ;
    END
  END out1[76]
  PIN out1[75]
    DIRECTION OUTPUT ;
    USE SIGNAL ;
    PORT
      LAYER M4 ;
        RECT 552.4500 780.8800 552.5500 781.4000 ;
    END
  END out1[75]
  PIN out1[74]
    DIRECTION OUTPUT ;
    USE SIGNAL ;
    PORT
      LAYER M4 ;
        RECT 554.4500 780.8800 554.5500 781.4000 ;
    END
  END out1[74]
  PIN out1[73]
    DIRECTION OUTPUT ;
    USE SIGNAL ;
    PORT
      LAYER M4 ;
        RECT 556.4500 780.8800 556.5500 781.4000 ;
    END
  END out1[73]
  PIN out1[72]
    DIRECTION OUTPUT ;
    USE SIGNAL ;
    PORT
      LAYER M4 ;
        RECT 558.4500 780.8800 558.5500 781.4000 ;
    END
  END out1[72]
  PIN out1[71]
    DIRECTION OUTPUT ;
    USE SIGNAL ;
    PORT
      LAYER M4 ;
        RECT 560.4500 780.8800 560.5500 781.4000 ;
    END
  END out1[71]
  PIN out1[70]
    DIRECTION OUTPUT ;
    USE SIGNAL ;
    PORT
      LAYER M4 ;
        RECT 562.4500 780.8800 562.5500 781.4000 ;
    END
  END out1[70]
  PIN out1[69]
    DIRECTION OUTPUT ;
    USE SIGNAL ;
    PORT
      LAYER M4 ;
        RECT 564.4500 780.8800 564.5500 781.4000 ;
    END
  END out1[69]
  PIN out1[68]
    DIRECTION OUTPUT ;
    USE SIGNAL ;
    PORT
      LAYER M4 ;
        RECT 566.4500 780.8800 566.5500 781.4000 ;
    END
  END out1[68]
  PIN out1[67]
    DIRECTION OUTPUT ;
    USE SIGNAL ;
    PORT
      LAYER M4 ;
        RECT 568.4500 780.8800 568.5500 781.4000 ;
    END
  END out1[67]
  PIN out1[66]
    DIRECTION OUTPUT ;
    USE SIGNAL ;
    PORT
      LAYER M4 ;
        RECT 570.4500 780.8800 570.5500 781.4000 ;
    END
  END out1[66]
  PIN out1[65]
    DIRECTION OUTPUT ;
    USE SIGNAL ;
    PORT
      LAYER M4 ;
        RECT 572.4500 780.8800 572.5500 781.4000 ;
    END
  END out1[65]
  PIN out1[64]
    DIRECTION OUTPUT ;
    USE SIGNAL ;
    PORT
      LAYER M4 ;
        RECT 574.4500 780.8800 574.5500 781.4000 ;
    END
  END out1[64]
  PIN out1[63]
    DIRECTION OUTPUT ;
    USE SIGNAL ;
    PORT
      LAYER M4 ;
        RECT 576.4500 780.8800 576.5500 781.4000 ;
    END
  END out1[63]
  PIN out1[62]
    DIRECTION OUTPUT ;
    USE SIGNAL ;
    PORT
      LAYER M4 ;
        RECT 578.4500 780.8800 578.5500 781.4000 ;
    END
  END out1[62]
  PIN out1[61]
    DIRECTION OUTPUT ;
    USE SIGNAL ;
    PORT
      LAYER M4 ;
        RECT 580.4500 780.8800 580.5500 781.4000 ;
    END
  END out1[61]
  PIN out1[60]
    DIRECTION OUTPUT ;
    USE SIGNAL ;
    PORT
      LAYER M4 ;
        RECT 582.4500 780.8800 582.5500 781.4000 ;
    END
  END out1[60]
  PIN out1[59]
    DIRECTION OUTPUT ;
    USE SIGNAL ;
    PORT
      LAYER M4 ;
        RECT 584.4500 780.8800 584.5500 781.4000 ;
    END
  END out1[59]
  PIN out1[58]
    DIRECTION OUTPUT ;
    USE SIGNAL ;
    PORT
      LAYER M4 ;
        RECT 586.4500 780.8800 586.5500 781.4000 ;
    END
  END out1[58]
  PIN out1[57]
    DIRECTION OUTPUT ;
    USE SIGNAL ;
    PORT
      LAYER M4 ;
        RECT 588.4500 780.8800 588.5500 781.4000 ;
    END
  END out1[57]
  PIN out1[56]
    DIRECTION OUTPUT ;
    USE SIGNAL ;
    PORT
      LAYER M4 ;
        RECT 590.4500 780.8800 590.5500 781.4000 ;
    END
  END out1[56]
  PIN out1[55]
    DIRECTION OUTPUT ;
    USE SIGNAL ;
    PORT
      LAYER M4 ;
        RECT 592.4500 780.8800 592.5500 781.4000 ;
    END
  END out1[55]
  PIN out1[54]
    DIRECTION OUTPUT ;
    USE SIGNAL ;
    PORT
      LAYER M4 ;
        RECT 594.4500 780.8800 594.5500 781.4000 ;
    END
  END out1[54]
  PIN out1[53]
    DIRECTION OUTPUT ;
    USE SIGNAL ;
    PORT
      LAYER M4 ;
        RECT 596.4500 780.8800 596.5500 781.4000 ;
    END
  END out1[53]
  PIN out1[52]
    DIRECTION OUTPUT ;
    USE SIGNAL ;
    PORT
      LAYER M4 ;
        RECT 598.4500 780.8800 598.5500 781.4000 ;
    END
  END out1[52]
  PIN out1[51]
    DIRECTION OUTPUT ;
    USE SIGNAL ;
    PORT
      LAYER M4 ;
        RECT 600.4500 780.8800 600.5500 781.4000 ;
    END
  END out1[51]
  PIN out1[50]
    DIRECTION OUTPUT ;
    USE SIGNAL ;
    PORT
      LAYER M4 ;
        RECT 602.4500 780.8800 602.5500 781.4000 ;
    END
  END out1[50]
  PIN out1[49]
    DIRECTION OUTPUT ;
    USE SIGNAL ;
    PORT
      LAYER M4 ;
        RECT 604.4500 780.8800 604.5500 781.4000 ;
    END
  END out1[49]
  PIN out1[48]
    DIRECTION OUTPUT ;
    USE SIGNAL ;
    PORT
      LAYER M4 ;
        RECT 606.4500 780.8800 606.5500 781.4000 ;
    END
  END out1[48]
  PIN out1[47]
    DIRECTION OUTPUT ;
    USE SIGNAL ;
    PORT
      LAYER M4 ;
        RECT 608.4500 780.8800 608.5500 781.4000 ;
    END
  END out1[47]
  PIN out1[46]
    DIRECTION OUTPUT ;
    USE SIGNAL ;
    PORT
      LAYER M4 ;
        RECT 610.4500 780.8800 610.5500 781.4000 ;
    END
  END out1[46]
  PIN out1[45]
    DIRECTION OUTPUT ;
    USE SIGNAL ;
    PORT
      LAYER M4 ;
        RECT 612.4500 780.8800 612.5500 781.4000 ;
    END
  END out1[45]
  PIN out1[44]
    DIRECTION OUTPUT ;
    USE SIGNAL ;
    PORT
      LAYER M4 ;
        RECT 614.4500 780.8800 614.5500 781.4000 ;
    END
  END out1[44]
  PIN out1[43]
    DIRECTION OUTPUT ;
    USE SIGNAL ;
    PORT
      LAYER M4 ;
        RECT 616.4500 780.8800 616.5500 781.4000 ;
    END
  END out1[43]
  PIN out1[42]
    DIRECTION OUTPUT ;
    USE SIGNAL ;
    PORT
      LAYER M4 ;
        RECT 618.4500 780.8800 618.5500 781.4000 ;
    END
  END out1[42]
  PIN out1[41]
    DIRECTION OUTPUT ;
    USE SIGNAL ;
    PORT
      LAYER M4 ;
        RECT 620.4500 780.8800 620.5500 781.4000 ;
    END
  END out1[41]
  PIN out1[40]
    DIRECTION OUTPUT ;
    USE SIGNAL ;
    PORT
      LAYER M4 ;
        RECT 622.4500 780.8800 622.5500 781.4000 ;
    END
  END out1[40]
  PIN out1[39]
    DIRECTION OUTPUT ;
    USE SIGNAL ;
    PORT
      LAYER M4 ;
        RECT 624.4500 780.8800 624.5500 781.4000 ;
    END
  END out1[39]
  PIN out1[38]
    DIRECTION OUTPUT ;
    USE SIGNAL ;
    PORT
      LAYER M4 ;
        RECT 626.4500 780.8800 626.5500 781.4000 ;
    END
  END out1[38]
  PIN out1[37]
    DIRECTION OUTPUT ;
    USE SIGNAL ;
    PORT
      LAYER M4 ;
        RECT 628.4500 780.8800 628.5500 781.4000 ;
    END
  END out1[37]
  PIN out1[36]
    DIRECTION OUTPUT ;
    USE SIGNAL ;
    PORT
      LAYER M4 ;
        RECT 630.4500 780.8800 630.5500 781.4000 ;
    END
  END out1[36]
  PIN out1[35]
    DIRECTION OUTPUT ;
    USE SIGNAL ;
    PORT
      LAYER M4 ;
        RECT 632.4500 780.8800 632.5500 781.4000 ;
    END
  END out1[35]
  PIN out1[34]
    DIRECTION OUTPUT ;
    USE SIGNAL ;
    PORT
      LAYER M4 ;
        RECT 634.4500 780.8800 634.5500 781.4000 ;
    END
  END out1[34]
  PIN out1[33]
    DIRECTION OUTPUT ;
    USE SIGNAL ;
    PORT
      LAYER M4 ;
        RECT 636.4500 780.8800 636.5500 781.4000 ;
    END
  END out1[33]
  PIN out1[32]
    DIRECTION OUTPUT ;
    USE SIGNAL ;
    PORT
      LAYER M4 ;
        RECT 638.4500 780.8800 638.5500 781.4000 ;
    END
  END out1[32]
  PIN out1[31]
    DIRECTION OUTPUT ;
    USE SIGNAL ;
    PORT
      LAYER M4 ;
        RECT 640.4500 780.8800 640.5500 781.4000 ;
    END
  END out1[31]
  PIN out1[30]
    DIRECTION OUTPUT ;
    USE SIGNAL ;
    PORT
      LAYER M4 ;
        RECT 642.4500 780.8800 642.5500 781.4000 ;
    END
  END out1[30]
  PIN out1[29]
    DIRECTION OUTPUT ;
    USE SIGNAL ;
    PORT
      LAYER M4 ;
        RECT 644.4500 780.8800 644.5500 781.4000 ;
    END
  END out1[29]
  PIN out1[28]
    DIRECTION OUTPUT ;
    USE SIGNAL ;
    PORT
      LAYER M4 ;
        RECT 646.4500 780.8800 646.5500 781.4000 ;
    END
  END out1[28]
  PIN out1[27]
    DIRECTION OUTPUT ;
    USE SIGNAL ;
    PORT
      LAYER M4 ;
        RECT 648.4500 780.8800 648.5500 781.4000 ;
    END
  END out1[27]
  PIN out1[26]
    DIRECTION OUTPUT ;
    USE SIGNAL ;
    PORT
      LAYER M4 ;
        RECT 650.4500 780.8800 650.5500 781.4000 ;
    END
  END out1[26]
  PIN out1[25]
    DIRECTION OUTPUT ;
    USE SIGNAL ;
    PORT
      LAYER M4 ;
        RECT 652.4500 780.8800 652.5500 781.4000 ;
    END
  END out1[25]
  PIN out1[24]
    DIRECTION OUTPUT ;
    USE SIGNAL ;
    PORT
      LAYER M4 ;
        RECT 654.4500 780.8800 654.5500 781.4000 ;
    END
  END out1[24]
  PIN out1[23]
    DIRECTION OUTPUT ;
    USE SIGNAL ;
    PORT
      LAYER M4 ;
        RECT 656.4500 780.8800 656.5500 781.4000 ;
    END
  END out1[23]
  PIN out1[22]
    DIRECTION OUTPUT ;
    USE SIGNAL ;
    PORT
      LAYER M4 ;
        RECT 658.4500 780.8800 658.5500 781.4000 ;
    END
  END out1[22]
  PIN out1[21]
    DIRECTION OUTPUT ;
    USE SIGNAL ;
    PORT
      LAYER M4 ;
        RECT 660.4500 780.8800 660.5500 781.4000 ;
    END
  END out1[21]
  PIN out1[20]
    DIRECTION OUTPUT ;
    USE SIGNAL ;
    PORT
      LAYER M4 ;
        RECT 662.4500 780.8800 662.5500 781.4000 ;
    END
  END out1[20]
  PIN out1[19]
    DIRECTION OUTPUT ;
    USE SIGNAL ;
    PORT
      LAYER M4 ;
        RECT 664.4500 780.8800 664.5500 781.4000 ;
    END
  END out1[19]
  PIN out1[18]
    DIRECTION OUTPUT ;
    USE SIGNAL ;
    PORT
      LAYER M4 ;
        RECT 666.4500 780.8800 666.5500 781.4000 ;
    END
  END out1[18]
  PIN out1[17]
    DIRECTION OUTPUT ;
    USE SIGNAL ;
    PORT
      LAYER M4 ;
        RECT 668.4500 780.8800 668.5500 781.4000 ;
    END
  END out1[17]
  PIN out1[16]
    DIRECTION OUTPUT ;
    USE SIGNAL ;
    PORT
      LAYER M4 ;
        RECT 670.4500 780.8800 670.5500 781.4000 ;
    END
  END out1[16]
  PIN out1[15]
    DIRECTION OUTPUT ;
    USE SIGNAL ;
    PORT
      LAYER M4 ;
        RECT 672.4500 780.8800 672.5500 781.4000 ;
    END
  END out1[15]
  PIN out1[14]
    DIRECTION OUTPUT ;
    USE SIGNAL ;
    PORT
      LAYER M4 ;
        RECT 674.4500 780.8800 674.5500 781.4000 ;
    END
  END out1[14]
  PIN out1[13]
    DIRECTION OUTPUT ;
    USE SIGNAL ;
    PORT
      LAYER M4 ;
        RECT 676.4500 780.8800 676.5500 781.4000 ;
    END
  END out1[13]
  PIN out1[12]
    DIRECTION OUTPUT ;
    USE SIGNAL ;
    PORT
      LAYER M4 ;
        RECT 678.4500 780.8800 678.5500 781.4000 ;
    END
  END out1[12]
  PIN out1[11]
    DIRECTION OUTPUT ;
    USE SIGNAL ;
    PORT
      LAYER M4 ;
        RECT 680.4500 780.8800 680.5500 781.4000 ;
    END
  END out1[11]
  PIN out1[10]
    DIRECTION OUTPUT ;
    USE SIGNAL ;
    PORT
      LAYER M4 ;
        RECT 682.4500 780.8800 682.5500 781.4000 ;
    END
  END out1[10]
  PIN out1[9]
    DIRECTION OUTPUT ;
    USE SIGNAL ;
    PORT
      LAYER M4 ;
        RECT 684.4500 780.8800 684.5500 781.4000 ;
    END
  END out1[9]
  PIN out1[8]
    DIRECTION OUTPUT ;
    USE SIGNAL ;
    PORT
      LAYER M4 ;
        RECT 686.4500 780.8800 686.5500 781.4000 ;
    END
  END out1[8]
  PIN out1[7]
    DIRECTION OUTPUT ;
    USE SIGNAL ;
    PORT
      LAYER M4 ;
        RECT 688.4500 780.8800 688.5500 781.4000 ;
    END
  END out1[7]
  PIN out1[6]
    DIRECTION OUTPUT ;
    USE SIGNAL ;
    PORT
      LAYER M4 ;
        RECT 690.4500 780.8800 690.5500 781.4000 ;
    END
  END out1[6]
  PIN out1[5]
    DIRECTION OUTPUT ;
    USE SIGNAL ;
    PORT
      LAYER M4 ;
        RECT 692.4500 780.8800 692.5500 781.4000 ;
    END
  END out1[5]
  PIN out1[4]
    DIRECTION OUTPUT ;
    USE SIGNAL ;
    PORT
      LAYER M4 ;
        RECT 694.4500 780.8800 694.5500 781.4000 ;
    END
  END out1[4]
  PIN out1[3]
    DIRECTION OUTPUT ;
    USE SIGNAL ;
    PORT
      LAYER M4 ;
        RECT 696.4500 780.8800 696.5500 781.4000 ;
    END
  END out1[3]
  PIN out1[2]
    DIRECTION OUTPUT ;
    USE SIGNAL ;
    PORT
      LAYER M4 ;
        RECT 698.4500 780.8800 698.5500 781.4000 ;
    END
  END out1[2]
  PIN out1[1]
    DIRECTION OUTPUT ;
    USE SIGNAL ;
    PORT
      LAYER M4 ;
        RECT 700.4500 780.8800 700.5500 781.4000 ;
    END
  END out1[1]
  PIN out1[0]
    DIRECTION OUTPUT ;
    USE SIGNAL ;
    PORT
      LAYER M4 ;
        RECT 702.4500 780.8800 702.5500 781.4000 ;
    END
  END out1[0]
  PIN status0[3]
    DIRECTION OUTPUT ;
    USE SIGNAL ;
    PORT
      LAYER M4 ;
        RECT 704.4500 780.8800 704.5500 781.4000 ;
    END
  END status0[3]
  PIN status0[2]
    DIRECTION OUTPUT ;
    USE SIGNAL ;
    PORT
      LAYER M4 ;
        RECT 706.4500 780.8800 706.5500 781.4000 ;
    END
  END status0[2]
  PIN status0[1]
    DIRECTION OUTPUT ;
    USE SIGNAL ;
    PORT
      LAYER M4 ;
        RECT 708.4500 780.8800 708.5500 781.4000 ;
    END
  END status0[1]
  PIN status0[0]
    DIRECTION OUTPUT ;
    USE SIGNAL ;
    PORT
      LAYER M4 ;
        RECT 710.4500 780.8800 710.5500 781.4000 ;
    END
  END status0[0]
  PIN status1[3]
    DIRECTION OUTPUT ;
    USE SIGNAL ;
    PORT
      LAYER M4 ;
        RECT 712.4500 780.8800 712.5500 781.4000 ;
    END
  END status1[3]
  PIN status1[2]
    DIRECTION OUTPUT ;
    USE SIGNAL ;
    PORT
      LAYER M4 ;
        RECT 714.4500 780.8800 714.5500 781.4000 ;
    END
  END status1[2]
  PIN status1[1]
    DIRECTION OUTPUT ;
    USE SIGNAL ;
    PORT
      LAYER M4 ;
        RECT 716.4500 780.8800 716.5500 781.4000 ;
    END
  END status1[1]
  PIN status1[0]
    DIRECTION OUTPUT ;
    USE SIGNAL ;
    PORT
      LAYER M4 ;
        RECT 718.4500 780.8800 718.5500 781.4000 ;
    END
  END status1[0]
  OBS
    LAYER M1 ;
      RECT 0.0000 0.0000 783.2000 781.4000 ;
    LAYER M2 ;
      RECT 0.0000 0.0000 783.2000 781.4000 ;
    LAYER M3 ;
      RECT 0.0000 450.9500 783.2000 781.4000 ;
      RECT 0.0000 450.7500 782.5800 450.9500 ;
      RECT 0.6200 450.6500 782.5800 450.7500 ;
      RECT 0.6200 450.4500 783.2000 450.6500 ;
      RECT 0.0000 430.9500 783.2000 450.4500 ;
      RECT 0.0000 430.7500 782.5800 430.9500 ;
      RECT 0.6200 430.6500 782.5800 430.7500 ;
      RECT 0.6200 430.4500 783.2000 430.6500 ;
      RECT 0.0000 410.9500 783.2000 430.4500 ;
      RECT 0.0000 410.7500 782.5800 410.9500 ;
      RECT 0.6200 410.6500 782.5800 410.7500 ;
      RECT 0.6200 410.4500 783.2000 410.6500 ;
      RECT 0.0000 390.9500 783.2000 410.4500 ;
      RECT 0.0000 390.7500 782.5800 390.9500 ;
      RECT 0.6200 390.6500 782.5800 390.7500 ;
      RECT 0.6200 390.4500 783.2000 390.6500 ;
      RECT 0.0000 370.9500 783.2000 390.4500 ;
      RECT 0.0000 370.7500 782.5800 370.9500 ;
      RECT 0.6200 370.6500 782.5800 370.7500 ;
      RECT 0.6200 370.4500 783.2000 370.6500 ;
      RECT 0.0000 350.9500 783.2000 370.4500 ;
      RECT 0.0000 350.7500 782.5800 350.9500 ;
      RECT 0.6200 350.6500 782.5800 350.7500 ;
      RECT 0.6200 350.4500 783.2000 350.6500 ;
      RECT 0.0000 330.9500 783.2000 350.4500 ;
      RECT 0.0000 330.7500 782.5800 330.9500 ;
      RECT 0.6200 330.6500 782.5800 330.7500 ;
      RECT 0.6200 330.4500 783.2000 330.6500 ;
      RECT 0.0000 0.0000 783.2000 330.4500 ;
    LAYER M4 ;
      RECT 718.6500 780.7800 783.2000 781.4000 ;
      RECT 716.6500 780.7800 718.3500 781.4000 ;
      RECT 714.6500 780.7800 716.3500 781.4000 ;
      RECT 712.6500 780.7800 714.3500 781.4000 ;
      RECT 710.6500 780.7800 712.3500 781.4000 ;
      RECT 708.6500 780.7800 710.3500 781.4000 ;
      RECT 706.6500 780.7800 708.3500 781.4000 ;
      RECT 704.6500 780.7800 706.3500 781.4000 ;
      RECT 702.6500 780.7800 704.3500 781.4000 ;
      RECT 700.6500 780.7800 702.3500 781.4000 ;
      RECT 698.6500 780.7800 700.3500 781.4000 ;
      RECT 696.6500 780.7800 698.3500 781.4000 ;
      RECT 694.6500 780.7800 696.3500 781.4000 ;
      RECT 692.6500 780.7800 694.3500 781.4000 ;
      RECT 690.6500 780.7800 692.3500 781.4000 ;
      RECT 688.6500 780.7800 690.3500 781.4000 ;
      RECT 686.6500 780.7800 688.3500 781.4000 ;
      RECT 684.6500 780.7800 686.3500 781.4000 ;
      RECT 682.6500 780.7800 684.3500 781.4000 ;
      RECT 680.6500 780.7800 682.3500 781.4000 ;
      RECT 678.6500 780.7800 680.3500 781.4000 ;
      RECT 676.6500 780.7800 678.3500 781.4000 ;
      RECT 674.6500 780.7800 676.3500 781.4000 ;
      RECT 672.6500 780.7800 674.3500 781.4000 ;
      RECT 670.6500 780.7800 672.3500 781.4000 ;
      RECT 668.6500 780.7800 670.3500 781.4000 ;
      RECT 666.6500 780.7800 668.3500 781.4000 ;
      RECT 664.6500 780.7800 666.3500 781.4000 ;
      RECT 662.6500 780.7800 664.3500 781.4000 ;
      RECT 660.6500 780.7800 662.3500 781.4000 ;
      RECT 658.6500 780.7800 660.3500 781.4000 ;
      RECT 656.6500 780.7800 658.3500 781.4000 ;
      RECT 654.6500 780.7800 656.3500 781.4000 ;
      RECT 652.6500 780.7800 654.3500 781.4000 ;
      RECT 650.6500 780.7800 652.3500 781.4000 ;
      RECT 648.6500 780.7800 650.3500 781.4000 ;
      RECT 646.6500 780.7800 648.3500 781.4000 ;
      RECT 644.6500 780.7800 646.3500 781.4000 ;
      RECT 642.6500 780.7800 644.3500 781.4000 ;
      RECT 640.6500 780.7800 642.3500 781.4000 ;
      RECT 638.6500 780.7800 640.3500 781.4000 ;
      RECT 636.6500 780.7800 638.3500 781.4000 ;
      RECT 634.6500 780.7800 636.3500 781.4000 ;
      RECT 632.6500 780.7800 634.3500 781.4000 ;
      RECT 630.6500 780.7800 632.3500 781.4000 ;
      RECT 628.6500 780.7800 630.3500 781.4000 ;
      RECT 626.6500 780.7800 628.3500 781.4000 ;
      RECT 624.6500 780.7800 626.3500 781.4000 ;
      RECT 622.6500 780.7800 624.3500 781.4000 ;
      RECT 620.6500 780.7800 622.3500 781.4000 ;
      RECT 618.6500 780.7800 620.3500 781.4000 ;
      RECT 616.6500 780.7800 618.3500 781.4000 ;
      RECT 614.6500 780.7800 616.3500 781.4000 ;
      RECT 612.6500 780.7800 614.3500 781.4000 ;
      RECT 610.6500 780.7800 612.3500 781.4000 ;
      RECT 608.6500 780.7800 610.3500 781.4000 ;
      RECT 606.6500 780.7800 608.3500 781.4000 ;
      RECT 604.6500 780.7800 606.3500 781.4000 ;
      RECT 602.6500 780.7800 604.3500 781.4000 ;
      RECT 600.6500 780.7800 602.3500 781.4000 ;
      RECT 598.6500 780.7800 600.3500 781.4000 ;
      RECT 596.6500 780.7800 598.3500 781.4000 ;
      RECT 594.6500 780.7800 596.3500 781.4000 ;
      RECT 592.6500 780.7800 594.3500 781.4000 ;
      RECT 590.6500 780.7800 592.3500 781.4000 ;
      RECT 588.6500 780.7800 590.3500 781.4000 ;
      RECT 586.6500 780.7800 588.3500 781.4000 ;
      RECT 584.6500 780.7800 586.3500 781.4000 ;
      RECT 582.6500 780.7800 584.3500 781.4000 ;
      RECT 580.6500 780.7800 582.3500 781.4000 ;
      RECT 578.6500 780.7800 580.3500 781.4000 ;
      RECT 576.6500 780.7800 578.3500 781.4000 ;
      RECT 574.6500 780.7800 576.3500 781.4000 ;
      RECT 572.6500 780.7800 574.3500 781.4000 ;
      RECT 570.6500 780.7800 572.3500 781.4000 ;
      RECT 568.6500 780.7800 570.3500 781.4000 ;
      RECT 566.6500 780.7800 568.3500 781.4000 ;
      RECT 564.6500 780.7800 566.3500 781.4000 ;
      RECT 562.6500 780.7800 564.3500 781.4000 ;
      RECT 560.6500 780.7800 562.3500 781.4000 ;
      RECT 558.6500 780.7800 560.3500 781.4000 ;
      RECT 556.6500 780.7800 558.3500 781.4000 ;
      RECT 554.6500 780.7800 556.3500 781.4000 ;
      RECT 552.6500 780.7800 554.3500 781.4000 ;
      RECT 550.6500 780.7800 552.3500 781.4000 ;
      RECT 548.6500 780.7800 550.3500 781.4000 ;
      RECT 546.6500 780.7800 548.3500 781.4000 ;
      RECT 544.6500 780.7800 546.3500 781.4000 ;
      RECT 542.6500 780.7800 544.3500 781.4000 ;
      RECT 540.6500 780.7800 542.3500 781.4000 ;
      RECT 538.6500 780.7800 540.3500 781.4000 ;
      RECT 536.6500 780.7800 538.3500 781.4000 ;
      RECT 534.6500 780.7800 536.3500 781.4000 ;
      RECT 532.6500 780.7800 534.3500 781.4000 ;
      RECT 530.6500 780.7800 532.3500 781.4000 ;
      RECT 528.6500 780.7800 530.3500 781.4000 ;
      RECT 526.6500 780.7800 528.3500 781.4000 ;
      RECT 524.6500 780.7800 526.3500 781.4000 ;
      RECT 522.6500 780.7800 524.3500 781.4000 ;
      RECT 520.6500 780.7800 522.3500 781.4000 ;
      RECT 518.6500 780.7800 520.3500 781.4000 ;
      RECT 516.6500 780.7800 518.3500 781.4000 ;
      RECT 514.6500 780.7800 516.3500 781.4000 ;
      RECT 512.6500 780.7800 514.3500 781.4000 ;
      RECT 510.6500 780.7800 512.3500 781.4000 ;
      RECT 508.6500 780.7800 510.3500 781.4000 ;
      RECT 506.6500 780.7800 508.3500 781.4000 ;
      RECT 504.6500 780.7800 506.3500 781.4000 ;
      RECT 502.6500 780.7800 504.3500 781.4000 ;
      RECT 500.6500 780.7800 502.3500 781.4000 ;
      RECT 498.6500 780.7800 500.3500 781.4000 ;
      RECT 496.6500 780.7800 498.3500 781.4000 ;
      RECT 494.6500 780.7800 496.3500 781.4000 ;
      RECT 492.6500 780.7800 494.3500 781.4000 ;
      RECT 490.6500 780.7800 492.3500 781.4000 ;
      RECT 488.6500 780.7800 490.3500 781.4000 ;
      RECT 486.6500 780.7800 488.3500 781.4000 ;
      RECT 484.6500 780.7800 486.3500 781.4000 ;
      RECT 482.6500 780.7800 484.3500 781.4000 ;
      RECT 480.6500 780.7800 482.3500 781.4000 ;
      RECT 478.6500 780.7800 480.3500 781.4000 ;
      RECT 476.6500 780.7800 478.3500 781.4000 ;
      RECT 474.6500 780.7800 476.3500 781.4000 ;
      RECT 472.6500 780.7800 474.3500 781.4000 ;
      RECT 470.6500 780.7800 472.3500 781.4000 ;
      RECT 468.6500 780.7800 470.3500 781.4000 ;
      RECT 466.6500 780.7800 468.3500 781.4000 ;
      RECT 464.6500 780.7800 466.3500 781.4000 ;
      RECT 462.6500 780.7800 464.3500 781.4000 ;
      RECT 460.6500 780.7800 462.3500 781.4000 ;
      RECT 458.6500 780.7800 460.3500 781.4000 ;
      RECT 456.6500 780.7800 458.3500 781.4000 ;
      RECT 454.6500 780.7800 456.3500 781.4000 ;
      RECT 452.6500 780.7800 454.3500 781.4000 ;
      RECT 450.6500 780.7800 452.3500 781.4000 ;
      RECT 448.6500 780.7800 450.3500 781.4000 ;
      RECT 446.6500 780.7800 448.3500 781.4000 ;
      RECT 444.6500 780.7800 446.3500 781.4000 ;
      RECT 442.6500 780.7800 444.3500 781.4000 ;
      RECT 440.6500 780.7800 442.3500 781.4000 ;
      RECT 438.6500 780.7800 440.3500 781.4000 ;
      RECT 436.6500 780.7800 438.3500 781.4000 ;
      RECT 434.6500 780.7800 436.3500 781.4000 ;
      RECT 432.6500 780.7800 434.3500 781.4000 ;
      RECT 430.6500 780.7800 432.3500 781.4000 ;
      RECT 428.6500 780.7800 430.3500 781.4000 ;
      RECT 426.6500 780.7800 428.3500 781.4000 ;
      RECT 424.6500 780.7800 426.3500 781.4000 ;
      RECT 422.6500 780.7800 424.3500 781.4000 ;
      RECT 420.6500 780.7800 422.3500 781.4000 ;
      RECT 418.6500 780.7800 420.3500 781.4000 ;
      RECT 416.6500 780.7800 418.3500 781.4000 ;
      RECT 414.6500 780.7800 416.3500 781.4000 ;
      RECT 412.6500 780.7800 414.3500 781.4000 ;
      RECT 410.6500 780.7800 412.3500 781.4000 ;
      RECT 408.6500 780.7800 410.3500 781.4000 ;
      RECT 406.6500 780.7800 408.3500 781.4000 ;
      RECT 404.6500 780.7800 406.3500 781.4000 ;
      RECT 402.6500 780.7800 404.3500 781.4000 ;
      RECT 400.6500 780.7800 402.3500 781.4000 ;
      RECT 398.6500 780.7800 400.3500 781.4000 ;
      RECT 396.6500 780.7800 398.3500 781.4000 ;
      RECT 394.6500 780.7800 396.3500 781.4000 ;
      RECT 392.6500 780.7800 394.3500 781.4000 ;
      RECT 390.6500 780.7800 392.3500 781.4000 ;
      RECT 388.6500 780.7800 390.3500 781.4000 ;
      RECT 386.6500 780.7800 388.3500 781.4000 ;
      RECT 384.6500 780.7800 386.3500 781.4000 ;
      RECT 382.6500 780.7800 384.3500 781.4000 ;
      RECT 380.6500 780.7800 382.3500 781.4000 ;
      RECT 378.6500 780.7800 380.3500 781.4000 ;
      RECT 376.6500 780.7800 378.3500 781.4000 ;
      RECT 374.6500 780.7800 376.3500 781.4000 ;
      RECT 372.6500 780.7800 374.3500 781.4000 ;
      RECT 370.6500 780.7800 372.3500 781.4000 ;
      RECT 368.6500 780.7800 370.3500 781.4000 ;
      RECT 366.6500 780.7800 368.3500 781.4000 ;
      RECT 364.6500 780.7800 366.3500 781.4000 ;
      RECT 362.6500 780.7800 364.3500 781.4000 ;
      RECT 360.6500 780.7800 362.3500 781.4000 ;
      RECT 358.6500 780.7800 360.3500 781.4000 ;
      RECT 356.6500 780.7800 358.3500 781.4000 ;
      RECT 354.6500 780.7800 356.3500 781.4000 ;
      RECT 352.6500 780.7800 354.3500 781.4000 ;
      RECT 350.6500 780.7800 352.3500 781.4000 ;
      RECT 348.6500 780.7800 350.3500 781.4000 ;
      RECT 346.6500 780.7800 348.3500 781.4000 ;
      RECT 344.6500 780.7800 346.3500 781.4000 ;
      RECT 342.6500 780.7800 344.3500 781.4000 ;
      RECT 340.6500 780.7800 342.3500 781.4000 ;
      RECT 338.6500 780.7800 340.3500 781.4000 ;
      RECT 336.6500 780.7800 338.3500 781.4000 ;
      RECT 334.6500 780.7800 336.3500 781.4000 ;
      RECT 332.6500 780.7800 334.3500 781.4000 ;
      RECT 330.6500 780.7800 332.3500 781.4000 ;
      RECT 328.6500 780.7800 330.3500 781.4000 ;
      RECT 326.6500 780.7800 328.3500 781.4000 ;
      RECT 324.6500 780.7800 326.3500 781.4000 ;
      RECT 322.6500 780.7800 324.3500 781.4000 ;
      RECT 320.6500 780.7800 322.3500 781.4000 ;
      RECT 318.6500 780.7800 320.3500 781.4000 ;
      RECT 316.6500 780.7800 318.3500 781.4000 ;
      RECT 314.6500 780.7800 316.3500 781.4000 ;
      RECT 312.6500 780.7800 314.3500 781.4000 ;
      RECT 310.6500 780.7800 312.3500 781.4000 ;
      RECT 308.6500 780.7800 310.3500 781.4000 ;
      RECT 306.6500 780.7800 308.3500 781.4000 ;
      RECT 304.6500 780.7800 306.3500 781.4000 ;
      RECT 302.6500 780.7800 304.3500 781.4000 ;
      RECT 300.6500 780.7800 302.3500 781.4000 ;
      RECT 298.6500 780.7800 300.3500 781.4000 ;
      RECT 296.6500 780.7800 298.3500 781.4000 ;
      RECT 294.6500 780.7800 296.3500 781.4000 ;
      RECT 292.6500 780.7800 294.3500 781.4000 ;
      RECT 290.6500 780.7800 292.3500 781.4000 ;
      RECT 288.6500 780.7800 290.3500 781.4000 ;
      RECT 286.6500 780.7800 288.3500 781.4000 ;
      RECT 284.6500 780.7800 286.3500 781.4000 ;
      RECT 282.6500 780.7800 284.3500 781.4000 ;
      RECT 280.6500 780.7800 282.3500 781.4000 ;
      RECT 278.6500 780.7800 280.3500 781.4000 ;
      RECT 276.6500 780.7800 278.3500 781.4000 ;
      RECT 274.6500 780.7800 276.3500 781.4000 ;
      RECT 272.6500 780.7800 274.3500 781.4000 ;
      RECT 270.6500 780.7800 272.3500 781.4000 ;
      RECT 268.6500 780.7800 270.3500 781.4000 ;
      RECT 266.6500 780.7800 268.3500 781.4000 ;
      RECT 264.6500 780.7800 266.3500 781.4000 ;
      RECT 262.6500 780.7800 264.3500 781.4000 ;
      RECT 260.6500 780.7800 262.3500 781.4000 ;
      RECT 258.6500 780.7800 260.3500 781.4000 ;
      RECT 256.6500 780.7800 258.3500 781.4000 ;
      RECT 254.6500 780.7800 256.3500 781.4000 ;
      RECT 252.6500 780.7800 254.3500 781.4000 ;
      RECT 250.6500 780.7800 252.3500 781.4000 ;
      RECT 248.6500 780.7800 250.3500 781.4000 ;
      RECT 246.6500 780.7800 248.3500 781.4000 ;
      RECT 244.6500 780.7800 246.3500 781.4000 ;
      RECT 242.6500 780.7800 244.3500 781.4000 ;
      RECT 240.6500 780.7800 242.3500 781.4000 ;
      RECT 238.6500 780.7800 240.3500 781.4000 ;
      RECT 236.6500 780.7800 238.3500 781.4000 ;
      RECT 234.6500 780.7800 236.3500 781.4000 ;
      RECT 232.6500 780.7800 234.3500 781.4000 ;
      RECT 230.6500 780.7800 232.3500 781.4000 ;
      RECT 228.6500 780.7800 230.3500 781.4000 ;
      RECT 226.6500 780.7800 228.3500 781.4000 ;
      RECT 224.6500 780.7800 226.3500 781.4000 ;
      RECT 222.6500 780.7800 224.3500 781.4000 ;
      RECT 220.6500 780.7800 222.3500 781.4000 ;
      RECT 218.6500 780.7800 220.3500 781.4000 ;
      RECT 216.6500 780.7800 218.3500 781.4000 ;
      RECT 214.6500 780.7800 216.3500 781.4000 ;
      RECT 212.6500 780.7800 214.3500 781.4000 ;
      RECT 210.6500 780.7800 212.3500 781.4000 ;
      RECT 208.6500 780.7800 210.3500 781.4000 ;
      RECT 206.6500 780.7800 208.3500 781.4000 ;
      RECT 204.6500 780.7800 206.3500 781.4000 ;
      RECT 202.6500 780.7800 204.3500 781.4000 ;
      RECT 200.6500 780.7800 202.3500 781.4000 ;
      RECT 198.6500 780.7800 200.3500 781.4000 ;
      RECT 196.6500 780.7800 198.3500 781.4000 ;
      RECT 194.6500 780.7800 196.3500 781.4000 ;
      RECT 192.6500 780.7800 194.3500 781.4000 ;
      RECT 190.6500 780.7800 192.3500 781.4000 ;
      RECT 188.6500 780.7800 190.3500 781.4000 ;
      RECT 186.6500 780.7800 188.3500 781.4000 ;
      RECT 184.6500 780.7800 186.3500 781.4000 ;
      RECT 182.6500 780.7800 184.3500 781.4000 ;
      RECT 180.6500 780.7800 182.3500 781.4000 ;
      RECT 178.6500 780.7800 180.3500 781.4000 ;
      RECT 176.6500 780.7800 178.3500 781.4000 ;
      RECT 174.6500 780.7800 176.3500 781.4000 ;
      RECT 172.6500 780.7800 174.3500 781.4000 ;
      RECT 170.6500 780.7800 172.3500 781.4000 ;
      RECT 168.6500 780.7800 170.3500 781.4000 ;
      RECT 166.6500 780.7800 168.3500 781.4000 ;
      RECT 164.6500 780.7800 166.3500 781.4000 ;
      RECT 162.6500 780.7800 164.3500 781.4000 ;
      RECT 160.6500 780.7800 162.3500 781.4000 ;
      RECT 158.6500 780.7800 160.3500 781.4000 ;
      RECT 156.6500 780.7800 158.3500 781.4000 ;
      RECT 154.6500 780.7800 156.3500 781.4000 ;
      RECT 152.6500 780.7800 154.3500 781.4000 ;
      RECT 150.6500 780.7800 152.3500 781.4000 ;
      RECT 148.6500 780.7800 150.3500 781.4000 ;
      RECT 146.6500 780.7800 148.3500 781.4000 ;
      RECT 144.6500 780.7800 146.3500 781.4000 ;
      RECT 142.6500 780.7800 144.3500 781.4000 ;
      RECT 140.6500 780.7800 142.3500 781.4000 ;
      RECT 138.6500 780.7800 140.3500 781.4000 ;
      RECT 136.6500 780.7800 138.3500 781.4000 ;
      RECT 134.6500 780.7800 136.3500 781.4000 ;
      RECT 132.6500 780.7800 134.3500 781.4000 ;
      RECT 130.6500 780.7800 132.3500 781.4000 ;
      RECT 128.6500 780.7800 130.3500 781.4000 ;
      RECT 126.6500 780.7800 128.3500 781.4000 ;
      RECT 124.6500 780.7800 126.3500 781.4000 ;
      RECT 122.6500 780.7800 124.3500 781.4000 ;
      RECT 120.6500 780.7800 122.3500 781.4000 ;
      RECT 118.6500 780.7800 120.3500 781.4000 ;
      RECT 116.6500 780.7800 118.3500 781.4000 ;
      RECT 114.6500 780.7800 116.3500 781.4000 ;
      RECT 112.6500 780.7800 114.3500 781.4000 ;
      RECT 110.6500 780.7800 112.3500 781.4000 ;
      RECT 108.6500 780.7800 110.3500 781.4000 ;
      RECT 106.6500 780.7800 108.3500 781.4000 ;
      RECT 104.6500 780.7800 106.3500 781.4000 ;
      RECT 102.6500 780.7800 104.3500 781.4000 ;
      RECT 100.6500 780.7800 102.3500 781.4000 ;
      RECT 98.6500 780.7800 100.3500 781.4000 ;
      RECT 96.6500 780.7800 98.3500 781.4000 ;
      RECT 94.6500 780.7800 96.3500 781.4000 ;
      RECT 92.6500 780.7800 94.3500 781.4000 ;
      RECT 90.6500 780.7800 92.3500 781.4000 ;
      RECT 88.6500 780.7800 90.3500 781.4000 ;
      RECT 86.6500 780.7800 88.3500 781.4000 ;
      RECT 84.6500 780.7800 86.3500 781.4000 ;
      RECT 82.6500 780.7800 84.3500 781.4000 ;
      RECT 80.6500 780.7800 82.3500 781.4000 ;
      RECT 78.6500 780.7800 80.3500 781.4000 ;
      RECT 76.6500 780.7800 78.3500 781.4000 ;
      RECT 74.6500 780.7800 76.3500 781.4000 ;
      RECT 72.6500 780.7800 74.3500 781.4000 ;
      RECT 70.6500 780.7800 72.3500 781.4000 ;
      RECT 68.6500 780.7800 70.3500 781.4000 ;
      RECT 66.6500 780.7800 68.3500 781.4000 ;
      RECT 64.6500 780.7800 66.3500 781.4000 ;
      RECT 0.0000 780.7800 64.3500 781.4000 ;
      RECT 0.0000 0.6200 783.2000 780.7800 ;
      RECT 600.4500 0.0000 783.2000 0.6200 ;
      RECT 597.4500 0.0000 600.1500 0.6200 ;
      RECT 594.4500 0.0000 597.1500 0.6200 ;
      RECT 591.4500 0.0000 594.1500 0.6200 ;
      RECT 588.4500 0.0000 591.1500 0.6200 ;
      RECT 585.4500 0.0000 588.1500 0.6200 ;
      RECT 582.4500 0.0000 585.1500 0.6200 ;
      RECT 579.4500 0.0000 582.1500 0.6200 ;
      RECT 576.4500 0.0000 579.1500 0.6200 ;
      RECT 573.4500 0.0000 576.1500 0.6200 ;
      RECT 570.4500 0.0000 573.1500 0.6200 ;
      RECT 567.4500 0.0000 570.1500 0.6200 ;
      RECT 564.4500 0.0000 567.1500 0.6200 ;
      RECT 561.4500 0.0000 564.1500 0.6200 ;
      RECT 558.4500 0.0000 561.1500 0.6200 ;
      RECT 555.4500 0.0000 558.1500 0.6200 ;
      RECT 552.4500 0.0000 555.1500 0.6200 ;
      RECT 549.4500 0.0000 552.1500 0.6200 ;
      RECT 546.4500 0.0000 549.1500 0.6200 ;
      RECT 543.4500 0.0000 546.1500 0.6200 ;
      RECT 540.4500 0.0000 543.1500 0.6200 ;
      RECT 537.4500 0.0000 540.1500 0.6200 ;
      RECT 534.4500 0.0000 537.1500 0.6200 ;
      RECT 531.4500 0.0000 534.1500 0.6200 ;
      RECT 528.4500 0.0000 531.1500 0.6200 ;
      RECT 525.4500 0.0000 528.1500 0.6200 ;
      RECT 522.4500 0.0000 525.1500 0.6200 ;
      RECT 519.4500 0.0000 522.1500 0.6200 ;
      RECT 516.4500 0.0000 519.1500 0.6200 ;
      RECT 513.4500 0.0000 516.1500 0.6200 ;
      RECT 510.4500 0.0000 513.1500 0.6200 ;
      RECT 507.4500 0.0000 510.1500 0.6200 ;
      RECT 504.4500 0.0000 507.1500 0.6200 ;
      RECT 501.4500 0.0000 504.1500 0.6200 ;
      RECT 498.4500 0.0000 501.1500 0.6200 ;
      RECT 495.4500 0.0000 498.1500 0.6200 ;
      RECT 492.4500 0.0000 495.1500 0.6200 ;
      RECT 489.4500 0.0000 492.1500 0.6200 ;
      RECT 486.4500 0.0000 489.1500 0.6200 ;
      RECT 483.4500 0.0000 486.1500 0.6200 ;
      RECT 480.4500 0.0000 483.1500 0.6200 ;
      RECT 477.4500 0.0000 480.1500 0.6200 ;
      RECT 474.4500 0.0000 477.1500 0.6200 ;
      RECT 471.4500 0.0000 474.1500 0.6200 ;
      RECT 468.4500 0.0000 471.1500 0.6200 ;
      RECT 465.4500 0.0000 468.1500 0.6200 ;
      RECT 462.4500 0.0000 465.1500 0.6200 ;
      RECT 459.4500 0.0000 462.1500 0.6200 ;
      RECT 456.4500 0.0000 459.1500 0.6200 ;
      RECT 453.4500 0.0000 456.1500 0.6200 ;
      RECT 450.4500 0.0000 453.1500 0.6200 ;
      RECT 447.4500 0.0000 450.1500 0.6200 ;
      RECT 444.4500 0.0000 447.1500 0.6200 ;
      RECT 441.4500 0.0000 444.1500 0.6200 ;
      RECT 438.4500 0.0000 441.1500 0.6200 ;
      RECT 435.4500 0.0000 438.1500 0.6200 ;
      RECT 432.4500 0.0000 435.1500 0.6200 ;
      RECT 429.4500 0.0000 432.1500 0.6200 ;
      RECT 426.4500 0.0000 429.1500 0.6200 ;
      RECT 423.4500 0.0000 426.1500 0.6200 ;
      RECT 420.4500 0.0000 423.1500 0.6200 ;
      RECT 417.4500 0.0000 420.1500 0.6200 ;
      RECT 414.4500 0.0000 417.1500 0.6200 ;
      RECT 411.4500 0.0000 414.1500 0.6200 ;
      RECT 408.4500 0.0000 411.1500 0.6200 ;
      RECT 405.4500 0.0000 408.1500 0.6200 ;
      RECT 402.4500 0.0000 405.1500 0.6200 ;
      RECT 399.4500 0.0000 402.1500 0.6200 ;
      RECT 396.4500 0.0000 399.1500 0.6200 ;
      RECT 393.4500 0.0000 396.1500 0.6200 ;
      RECT 390.4500 0.0000 393.1500 0.6200 ;
      RECT 387.4500 0.0000 390.1500 0.6200 ;
      RECT 384.4500 0.0000 387.1500 0.6200 ;
      RECT 381.4500 0.0000 384.1500 0.6200 ;
      RECT 378.4500 0.0000 381.1500 0.6200 ;
      RECT 375.4500 0.0000 378.1500 0.6200 ;
      RECT 372.4500 0.0000 375.1500 0.6200 ;
      RECT 369.4500 0.0000 372.1500 0.6200 ;
      RECT 366.4500 0.0000 369.1500 0.6200 ;
      RECT 363.4500 0.0000 366.1500 0.6200 ;
      RECT 360.4500 0.0000 363.1500 0.6200 ;
      RECT 357.4500 0.0000 360.1500 0.6200 ;
      RECT 354.4500 0.0000 357.1500 0.6200 ;
      RECT 351.4500 0.0000 354.1500 0.6200 ;
      RECT 348.4500 0.0000 351.1500 0.6200 ;
      RECT 345.4500 0.0000 348.1500 0.6200 ;
      RECT 342.4500 0.0000 345.1500 0.6200 ;
      RECT 339.4500 0.0000 342.1500 0.6200 ;
      RECT 336.4500 0.0000 339.1500 0.6200 ;
      RECT 333.4500 0.0000 336.1500 0.6200 ;
      RECT 330.4500 0.0000 333.1500 0.6200 ;
      RECT 327.4500 0.0000 330.1500 0.6200 ;
      RECT 324.4500 0.0000 327.1500 0.6200 ;
      RECT 321.4500 0.0000 324.1500 0.6200 ;
      RECT 318.4500 0.0000 321.1500 0.6200 ;
      RECT 315.4500 0.0000 318.1500 0.6200 ;
      RECT 312.4500 0.0000 315.1500 0.6200 ;
      RECT 309.4500 0.0000 312.1500 0.6200 ;
      RECT 306.4500 0.0000 309.1500 0.6200 ;
      RECT 303.4500 0.0000 306.1500 0.6200 ;
      RECT 300.4500 0.0000 303.1500 0.6200 ;
      RECT 297.4500 0.0000 300.1500 0.6200 ;
      RECT 294.4500 0.0000 297.1500 0.6200 ;
      RECT 291.4500 0.0000 294.1500 0.6200 ;
      RECT 288.4500 0.0000 291.1500 0.6200 ;
      RECT 285.4500 0.0000 288.1500 0.6200 ;
      RECT 282.4500 0.0000 285.1500 0.6200 ;
      RECT 279.4500 0.0000 282.1500 0.6200 ;
      RECT 276.4500 0.0000 279.1500 0.6200 ;
      RECT 273.4500 0.0000 276.1500 0.6200 ;
      RECT 270.4500 0.0000 273.1500 0.6200 ;
      RECT 267.4500 0.0000 270.1500 0.6200 ;
      RECT 264.4500 0.0000 267.1500 0.6200 ;
      RECT 261.4500 0.0000 264.1500 0.6200 ;
      RECT 258.4500 0.0000 261.1500 0.6200 ;
      RECT 255.4500 0.0000 258.1500 0.6200 ;
      RECT 252.4500 0.0000 255.1500 0.6200 ;
      RECT 249.4500 0.0000 252.1500 0.6200 ;
      RECT 246.4500 0.0000 249.1500 0.6200 ;
      RECT 243.4500 0.0000 246.1500 0.6200 ;
      RECT 240.4500 0.0000 243.1500 0.6200 ;
      RECT 237.4500 0.0000 240.1500 0.6200 ;
      RECT 234.4500 0.0000 237.1500 0.6200 ;
      RECT 231.4500 0.0000 234.1500 0.6200 ;
      RECT 228.4500 0.0000 231.1500 0.6200 ;
      RECT 225.4500 0.0000 228.1500 0.6200 ;
      RECT 222.4500 0.0000 225.1500 0.6200 ;
      RECT 219.4500 0.0000 222.1500 0.6200 ;
      RECT 216.4500 0.0000 219.1500 0.6200 ;
      RECT 213.4500 0.0000 216.1500 0.6200 ;
      RECT 210.4500 0.0000 213.1500 0.6200 ;
      RECT 207.4500 0.0000 210.1500 0.6200 ;
      RECT 204.4500 0.0000 207.1500 0.6200 ;
      RECT 201.4500 0.0000 204.1500 0.6200 ;
      RECT 198.4500 0.0000 201.1500 0.6200 ;
      RECT 195.4500 0.0000 198.1500 0.6200 ;
      RECT 192.4500 0.0000 195.1500 0.6200 ;
      RECT 189.4500 0.0000 192.1500 0.6200 ;
      RECT 186.4500 0.0000 189.1500 0.6200 ;
      RECT 183.4500 0.0000 186.1500 0.6200 ;
      RECT 0.0000 0.0000 183.1500 0.6200 ;
    LAYER M5 ;
      RECT 0.0000 0.0000 783.2000 781.4000 ;
    LAYER M6 ;
      RECT 0.0000 0.0000 783.2000 781.4000 ;
    LAYER M7 ;
      RECT 0.0000 0.0000 783.2000 781.4000 ;
    LAYER M8 ;
      RECT 0.0000 0.0000 783.2000 781.4000 ;
  END
END fullchip

END LIBRARY
